VERSION 5.8 ;
BUSBITCHARS "[]" ;
DIVIDERCHAR "/" ;
UNITS
    DATABASE MICRONS 1000 ;
END UNITS

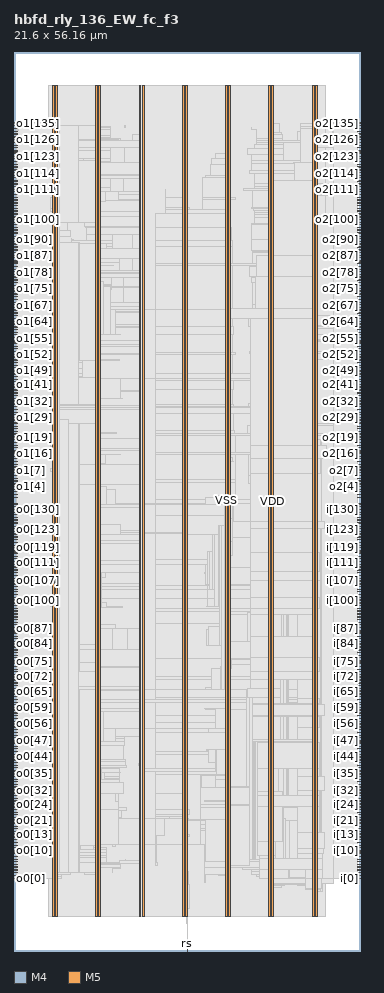
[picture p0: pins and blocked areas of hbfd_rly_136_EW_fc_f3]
MACRO hbfd_rly_136_EW_fc_f3
  FOREIGN hbfd_rly_136_EW_fc_f3 0 0 ;
  CLASS BLOCK ;
  SIZE 21.6 BY 56.16 ;
  PIN clk_in
    DIRECTION INPUT ;
    USE SIGNAL ;
    PORT
      LAYER M4 ;
        RECT  21.408 16.224 21.6 16.248 ;
    END
  END clk_in
  PIN clk_out0
    DIRECTION OUTPUT ;
    USE SIGNAL ;
    PORT
      LAYER M4 ;
        RECT  0 16.224 0.192 16.248 ;
    END
  END clk_out0
  PIN clk_out1
    DIRECTION OUTPUT ;
    USE SIGNAL ;
    PORT
      LAYER M4 ;
        RECT  0 39.984 0.192 40.008 ;
    END
  END clk_out1
  PIN clk_out2
    DIRECTION OUTPUT ;
    USE SIGNAL ;
    PORT
      LAYER M4 ;
        RECT  21.408 39.984 21.6 40.008 ;
    END
  END clk_out2
  PIN i[0]
    DIRECTION INPUT ;
    USE SIGNAL ;
    PORT
      LAYER M4 ;
        RECT  21.408 4.512 21.6 4.536 ;
    END
  END i[0]
  PIN i[100]
    DIRECTION INPUT ;
    USE SIGNAL ;
    PORT
      LAYER M4 ;
        RECT  21.408 21.888 21.6 21.912 ;
    END
  END i[100]
  PIN i[101]
    DIRECTION INPUT ;
    USE SIGNAL ;
    PORT
      LAYER M4 ;
        RECT  21.408 22.032 21.6 22.056 ;
    END
  END i[101]
  PIN i[102]
    DIRECTION INPUT ;
    USE SIGNAL ;
    PORT
      LAYER M4 ;
        RECT  21.408 22.224 21.6 22.248 ;
    END
  END i[102]
  PIN i[103]
    DIRECTION INPUT ;
    USE SIGNAL ;
    PORT
      LAYER M4 ;
        RECT  21.408 22.416 21.6 22.44 ;
    END
  END i[103]
  PIN i[104]
    DIRECTION INPUT ;
    USE SIGNAL ;
    PORT
      LAYER M4 ;
        RECT  21.408 22.56 21.6 22.584 ;
    END
  END i[104]
  PIN i[105]
    DIRECTION INPUT ;
    USE SIGNAL ;
    PORT
      LAYER M4 ;
        RECT  21.408 22.752 21.6 22.776 ;
    END
  END i[105]
  PIN i[106]
    DIRECTION INPUT ;
    USE SIGNAL ;
    PORT
      LAYER M4 ;
        RECT  21.408 22.896 21.6 22.92 ;
    END
  END i[106]
  PIN i[107]
    DIRECTION INPUT ;
    USE SIGNAL ;
    PORT
      LAYER M4 ;
        RECT  21.408 23.088 21.6 23.112 ;
    END
  END i[107]
  PIN i[108]
    DIRECTION INPUT ;
    USE SIGNAL ;
    PORT
      LAYER M4 ;
        RECT  21.408 23.232 21.6 23.256 ;
    END
  END i[108]
  PIN i[109]
    DIRECTION INPUT ;
    USE SIGNAL ;
    PORT
      LAYER M4 ;
        RECT  21.408 23.424 21.6 23.448 ;
    END
  END i[109]
  PIN i[10]
    DIRECTION INPUT ;
    USE SIGNAL ;
    PORT
      LAYER M4 ;
        RECT  21.408 6.24 21.6 6.264 ;
    END
  END i[10]
  PIN i[110]
    DIRECTION INPUT ;
    USE SIGNAL ;
    PORT
      LAYER M4 ;
        RECT  21.408 23.616 21.6 23.64 ;
    END
  END i[110]
  PIN i[111]
    DIRECTION INPUT ;
    USE SIGNAL ;
    PORT
      LAYER M4 ;
        RECT  21.408 23.76 21.6 23.784 ;
    END
  END i[111]
  PIN i[112]
    DIRECTION INPUT ;
    USE SIGNAL ;
    PORT
      LAYER M4 ;
        RECT  21.408 23.952 21.6 23.976 ;
    END
  END i[112]
  PIN i[113]
    DIRECTION INPUT ;
    USE SIGNAL ;
    PORT
      LAYER M4 ;
        RECT  21.408 24.096 21.6 24.12 ;
    END
  END i[113]
  PIN i[114]
    DIRECTION INPUT ;
    USE SIGNAL ;
    PORT
      LAYER M4 ;
        RECT  21.408 24.288 21.6 24.312 ;
    END
  END i[114]
  PIN i[115]
    DIRECTION INPUT ;
    USE SIGNAL ;
    PORT
      LAYER M4 ;
        RECT  21.408 24.48 21.6 24.504 ;
    END
  END i[115]
  PIN i[116]
    DIRECTION INPUT ;
    USE SIGNAL ;
    PORT
      LAYER M4 ;
        RECT  21.408 24.624 21.6 24.648 ;
    END
  END i[116]
  PIN i[117]
    DIRECTION INPUT ;
    USE SIGNAL ;
    PORT
      LAYER M4 ;
        RECT  21.408 24.816 21.6 24.84 ;
    END
  END i[117]
  PIN i[118]
    DIRECTION INPUT ;
    USE SIGNAL ;
    PORT
      LAYER M4 ;
        RECT  21.408 24.96 21.6 24.984 ;
    END
  END i[118]
  PIN i[119]
    DIRECTION INPUT ;
    USE SIGNAL ;
    PORT
      LAYER M4 ;
        RECT  21.408 25.152 21.6 25.176 ;
    END
  END i[119]
  PIN i[11]
    DIRECTION INPUT ;
    USE SIGNAL ;
    PORT
      LAYER M4 ;
        RECT  21.408 6.432 21.6 6.456 ;
    END
  END i[11]
  PIN i[120]
    DIRECTION INPUT ;
    USE SIGNAL ;
    PORT
      LAYER M4 ;
        RECT  21.408 25.296 21.6 25.32 ;
    END
  END i[120]
  PIN i[121]
    DIRECTION INPUT ;
    USE SIGNAL ;
    PORT
      LAYER M4 ;
        RECT  21.408 25.488 21.6 25.512 ;
    END
  END i[121]
  PIN i[122]
    DIRECTION INPUT ;
    USE SIGNAL ;
    PORT
      LAYER M4 ;
        RECT  21.408 25.68 21.6 25.704 ;
    END
  END i[122]
  PIN i[123]
    DIRECTION INPUT ;
    USE SIGNAL ;
    PORT
      LAYER M4 ;
        RECT  21.408 25.824 21.6 25.848 ;
    END
  END i[123]
  PIN i[124]
    DIRECTION INPUT ;
    USE SIGNAL ;
    PORT
      LAYER M4 ;
        RECT  21.408 26.016 21.6 26.04 ;
    END
  END i[124]
  PIN i[125]
    DIRECTION INPUT ;
    USE SIGNAL ;
    PORT
      LAYER M4 ;
        RECT  21.408 26.16 21.6 26.184 ;
    END
  END i[125]
  PIN i[126]
    DIRECTION INPUT ;
    USE SIGNAL ;
    PORT
      LAYER M4 ;
        RECT  21.408 26.352 21.6 26.376 ;
    END
  END i[126]
  PIN i[127]
    DIRECTION INPUT ;
    USE SIGNAL ;
    PORT
      LAYER M4 ;
        RECT  21.408 26.496 21.6 26.52 ;
    END
  END i[127]
  PIN i[128]
    DIRECTION INPUT ;
    USE SIGNAL ;
    PORT
      LAYER M4 ;
        RECT  21.408 26.688 21.6 26.712 ;
    END
  END i[128]
  PIN i[129]
    DIRECTION INPUT ;
    USE SIGNAL ;
    PORT
      LAYER M4 ;
        RECT  21.408 26.88 21.6 26.904 ;
    END
  END i[129]
  PIN i[12]
    DIRECTION INPUT ;
    USE SIGNAL ;
    PORT
      LAYER M4 ;
        RECT  21.408 6.576 21.6 6.6 ;
    END
  END i[12]
  PIN i[130]
    DIRECTION INPUT ;
    USE SIGNAL ;
    PORT
      LAYER M4 ;
        RECT  21.408 27.024 21.6 27.048 ;
    END
  END i[130]
  PIN i[131]
    DIRECTION INPUT ;
    USE SIGNAL ;
    PORT
      LAYER M4 ;
        RECT  21.408 27.216 21.6 27.24 ;
    END
  END i[131]
  PIN i[132]
    DIRECTION INPUT ;
    USE SIGNAL ;
    PORT
      LAYER M4 ;
        RECT  21.408 27.36 21.6 27.384 ;
    END
  END i[132]
  PIN i[133]
    DIRECTION INPUT ;
    USE SIGNAL ;
    PORT
      LAYER M4 ;
        RECT  21.408 27.552 21.6 27.576 ;
    END
  END i[133]
  PIN i[134]
    DIRECTION INPUT ;
    USE SIGNAL ;
    PORT
      LAYER M4 ;
        RECT  21.408 27.744 21.6 27.768 ;
    END
  END i[134]
  PIN i[135]
    DIRECTION INPUT ;
    USE SIGNAL ;
    PORT
      LAYER M4 ;
        RECT  21.408 27.888 21.6 27.912 ;
    END
  END i[135]
  PIN i[13]
    DIRECTION INPUT ;
    USE SIGNAL ;
    PORT
      LAYER M4 ;
        RECT  21.408 6.768 21.6 6.792 ;
    END
  END i[13]
  PIN i[14]
    DIRECTION INPUT ;
    USE SIGNAL ;
    PORT
      LAYER M4 ;
        RECT  21.408 6.96 21.6 6.984 ;
    END
  END i[14]
  PIN i[15]
    DIRECTION INPUT ;
    USE SIGNAL ;
    PORT
      LAYER M4 ;
        RECT  21.408 7.104 21.6 7.128 ;
    END
  END i[15]
  PIN i[16]
    DIRECTION INPUT ;
    USE SIGNAL ;
    PORT
      LAYER M4 ;
        RECT  21.408 7.296 21.6 7.32 ;
    END
  END i[16]
  PIN i[17]
    DIRECTION INPUT ;
    USE SIGNAL ;
    PORT
      LAYER M4 ;
        RECT  21.408 7.44 21.6 7.464 ;
    END
  END i[17]
  PIN i[18]
    DIRECTION INPUT ;
    USE SIGNAL ;
    PORT
      LAYER M4 ;
        RECT  21.408 7.632 21.6 7.656 ;
    END
  END i[18]
  PIN i[19]
    DIRECTION INPUT ;
    USE SIGNAL ;
    PORT
      LAYER M4 ;
        RECT  21.408 7.776 21.6 7.8 ;
    END
  END i[19]
  PIN i[1]
    DIRECTION INPUT ;
    USE SIGNAL ;
    PORT
      LAYER M4 ;
        RECT  21.408 4.704 21.6 4.728 ;
    END
  END i[1]
  PIN i[20]
    DIRECTION INPUT ;
    USE SIGNAL ;
    PORT
      LAYER M4 ;
        RECT  21.408 7.968 21.6 7.992 ;
    END
  END i[20]
  PIN i[21]
    DIRECTION INPUT ;
    USE SIGNAL ;
    PORT
      LAYER M4 ;
        RECT  21.408 8.16 21.6 8.184 ;
    END
  END i[21]
  PIN i[22]
    DIRECTION INPUT ;
    USE SIGNAL ;
    PORT
      LAYER M4 ;
        RECT  21.408 8.304 21.6 8.328 ;
    END
  END i[22]
  PIN i[23]
    DIRECTION INPUT ;
    USE SIGNAL ;
    PORT
      LAYER M4 ;
        RECT  21.408 8.496 21.6 8.52 ;
    END
  END i[23]
  PIN i[24]
    DIRECTION INPUT ;
    USE SIGNAL ;
    PORT
      LAYER M4 ;
        RECT  21.408 8.64 21.6 8.664 ;
    END
  END i[24]
  PIN i[25]
    DIRECTION INPUT ;
    USE SIGNAL ;
    PORT
      LAYER M4 ;
        RECT  21.408 8.832 21.6 8.856 ;
    END
  END i[25]
  PIN i[26]
    DIRECTION INPUT ;
    USE SIGNAL ;
    PORT
      LAYER M4 ;
        RECT  21.408 8.976 21.6 9 ;
    END
  END i[26]
  PIN i[27]
    DIRECTION INPUT ;
    USE SIGNAL ;
    PORT
      LAYER M4 ;
        RECT  21.408 9.168 21.6 9.192 ;
    END
  END i[27]
  PIN i[28]
    DIRECTION INPUT ;
    USE SIGNAL ;
    PORT
      LAYER M4 ;
        RECT  21.408 9.36 21.6 9.384 ;
    END
  END i[28]
  PIN i[29]
    DIRECTION INPUT ;
    USE SIGNAL ;
    PORT
      LAYER M4 ;
        RECT  21.408 9.504 21.6 9.528 ;
    END
  END i[29]
  PIN i[2]
    DIRECTION INPUT ;
    USE SIGNAL ;
    PORT
      LAYER M4 ;
        RECT  21.408 4.896 21.6 4.92 ;
    END
  END i[2]
  PIN i[30]
    DIRECTION INPUT ;
    USE SIGNAL ;
    PORT
      LAYER M4 ;
        RECT  21.408 9.696 21.6 9.72 ;
    END
  END i[30]
  PIN i[31]
    DIRECTION INPUT ;
    USE SIGNAL ;
    PORT
      LAYER M4 ;
        RECT  21.408 9.84 21.6 9.864 ;
    END
  END i[31]
  PIN i[32]
    DIRECTION INPUT ;
    USE SIGNAL ;
    PORT
      LAYER M4 ;
        RECT  21.408 10.032 21.6 10.056 ;
    END
  END i[32]
  PIN i[33]
    DIRECTION INPUT ;
    USE SIGNAL ;
    PORT
      LAYER M4 ;
        RECT  21.408 10.224 21.6 10.248 ;
    END
  END i[33]
  PIN i[34]
    DIRECTION INPUT ;
    USE SIGNAL ;
    PORT
      LAYER M4 ;
        RECT  21.408 10.368 21.6 10.392 ;
    END
  END i[34]
  PIN i[35]
    DIRECTION INPUT ;
    USE SIGNAL ;
    PORT
      LAYER M4 ;
        RECT  21.408 10.56 21.6 10.584 ;
    END
  END i[35]
  PIN i[36]
    DIRECTION INPUT ;
    USE SIGNAL ;
    PORT
      LAYER M4 ;
        RECT  21.408 10.704 21.6 10.728 ;
    END
  END i[36]
  PIN i[37]
    DIRECTION INPUT ;
    USE SIGNAL ;
    PORT
      LAYER M4 ;
        RECT  21.408 10.896 21.6 10.92 ;
    END
  END i[37]
  PIN i[38]
    DIRECTION INPUT ;
    USE SIGNAL ;
    PORT
      LAYER M4 ;
        RECT  21.408 11.04 21.6 11.064 ;
    END
  END i[38]
  PIN i[39]
    DIRECTION INPUT ;
    USE SIGNAL ;
    PORT
      LAYER M4 ;
        RECT  21.408 11.232 21.6 11.256 ;
    END
  END i[39]
  PIN i[3]
    DIRECTION INPUT ;
    USE SIGNAL ;
    PORT
      LAYER M4 ;
        RECT  21.408 5.04 21.6 5.064 ;
    END
  END i[3]
  PIN i[40]
    DIRECTION INPUT ;
    USE SIGNAL ;
    PORT
      LAYER M4 ;
        RECT  21.408 11.424 21.6 11.448 ;
    END
  END i[40]
  PIN i[41]
    DIRECTION INPUT ;
    USE SIGNAL ;
    PORT
      LAYER M4 ;
        RECT  21.408 11.568 21.6 11.592 ;
    END
  END i[41]
  PIN i[42]
    DIRECTION INPUT ;
    USE SIGNAL ;
    PORT
      LAYER M4 ;
        RECT  21.408 11.76 21.6 11.784 ;
    END
  END i[42]
  PIN i[43]
    DIRECTION INPUT ;
    USE SIGNAL ;
    PORT
      LAYER M4 ;
        RECT  21.408 11.904 21.6 11.928 ;
    END
  END i[43]
  PIN i[44]
    DIRECTION INPUT ;
    USE SIGNAL ;
    PORT
      LAYER M4 ;
        RECT  21.408 12.096 21.6 12.12 ;
    END
  END i[44]
  PIN i[45]
    DIRECTION INPUT ;
    USE SIGNAL ;
    PORT
      LAYER M4 ;
        RECT  21.408 12.24 21.6 12.264 ;
    END
  END i[45]
  PIN i[46]
    DIRECTION INPUT ;
    USE SIGNAL ;
    PORT
      LAYER M4 ;
        RECT  21.408 12.432 21.6 12.456 ;
    END
  END i[46]
  PIN i[47]
    DIRECTION INPUT ;
    USE SIGNAL ;
    PORT
      LAYER M4 ;
        RECT  21.408 12.624 21.6 12.648 ;
    END
  END i[47]
  PIN i[48]
    DIRECTION INPUT ;
    USE SIGNAL ;
    PORT
      LAYER M4 ;
        RECT  21.408 12.768 21.6 12.792 ;
    END
  END i[48]
  PIN i[49]
    DIRECTION INPUT ;
    USE SIGNAL ;
    PORT
      LAYER M4 ;
        RECT  21.408 12.96 21.6 12.984 ;
    END
  END i[49]
  PIN i[4]
    DIRECTION INPUT ;
    USE SIGNAL ;
    PORT
      LAYER M4 ;
        RECT  21.408 5.232 21.6 5.256 ;
    END
  END i[4]
  PIN i[50]
    DIRECTION INPUT ;
    USE SIGNAL ;
    PORT
      LAYER M4 ;
        RECT  21.408 13.104 21.6 13.128 ;
    END
  END i[50]
  PIN i[51]
    DIRECTION INPUT ;
    USE SIGNAL ;
    PORT
      LAYER M4 ;
        RECT  21.408 13.296 21.6 13.32 ;
    END
  END i[51]
  PIN i[52]
    DIRECTION INPUT ;
    USE SIGNAL ;
    PORT
      LAYER M4 ;
        RECT  21.408 13.44 21.6 13.464 ;
    END
  END i[52]
  PIN i[53]
    DIRECTION INPUT ;
    USE SIGNAL ;
    PORT
      LAYER M4 ;
        RECT  21.408 13.632 21.6 13.656 ;
    END
  END i[53]
  PIN i[54]
    DIRECTION INPUT ;
    USE SIGNAL ;
    PORT
      LAYER M4 ;
        RECT  21.408 13.824 21.6 13.848 ;
    END
  END i[54]
  PIN i[55]
    DIRECTION INPUT ;
    USE SIGNAL ;
    PORT
      LAYER M4 ;
        RECT  21.408 13.968 21.6 13.992 ;
    END
  END i[55]
  PIN i[56]
    DIRECTION INPUT ;
    USE SIGNAL ;
    PORT
      LAYER M4 ;
        RECT  21.408 14.16 21.6 14.184 ;
    END
  END i[56]
  PIN i[57]
    DIRECTION INPUT ;
    USE SIGNAL ;
    PORT
      LAYER M4 ;
        RECT  21.408 14.304 21.6 14.328 ;
    END
  END i[57]
  PIN i[58]
    DIRECTION INPUT ;
    USE SIGNAL ;
    PORT
      LAYER M4 ;
        RECT  21.408 14.496 21.6 14.52 ;
    END
  END i[58]
  PIN i[59]
    DIRECTION INPUT ;
    USE SIGNAL ;
    PORT
      LAYER M4 ;
        RECT  21.408 14.688 21.6 14.712 ;
    END
  END i[59]
  PIN i[5]
    DIRECTION INPUT ;
    USE SIGNAL ;
    PORT
      LAYER M4 ;
        RECT  21.408 5.376 21.6 5.4 ;
    END
  END i[5]
  PIN i[60]
    DIRECTION INPUT ;
    USE SIGNAL ;
    PORT
      LAYER M4 ;
        RECT  21.408 14.832 21.6 14.856 ;
    END
  END i[60]
  PIN i[61]
    DIRECTION INPUT ;
    USE SIGNAL ;
    PORT
      LAYER M4 ;
        RECT  21.408 15.024 21.6 15.048 ;
    END
  END i[61]
  PIN i[62]
    DIRECTION INPUT ;
    USE SIGNAL ;
    PORT
      LAYER M4 ;
        RECT  21.408 15.168 21.6 15.192 ;
    END
  END i[62]
  PIN i[63]
    DIRECTION INPUT ;
    USE SIGNAL ;
    PORT
      LAYER M4 ;
        RECT  21.408 15.36 21.6 15.384 ;
    END
  END i[63]
  PIN i[64]
    DIRECTION INPUT ;
    USE SIGNAL ;
    PORT
      LAYER M4 ;
        RECT  21.408 15.504 21.6 15.528 ;
    END
  END i[64]
  PIN i[65]
    DIRECTION INPUT ;
    USE SIGNAL ;
    PORT
      LAYER M4 ;
        RECT  21.408 15.696 21.6 15.72 ;
    END
  END i[65]
  PIN i[66]
    DIRECTION INPUT ;
    USE SIGNAL ;
    PORT
      LAYER M4 ;
        RECT  21.408 15.888 21.6 15.912 ;
    END
  END i[66]
  PIN i[67]
    DIRECTION INPUT ;
    USE SIGNAL ;
    PORT
      LAYER M4 ;
        RECT  21.408 16.032 21.6 16.056 ;
    END
  END i[67]
  PIN i[68]
    DIRECTION INPUT ;
    USE SIGNAL ;
    PORT
      LAYER M4 ;
        RECT  21.408 16.368 21.6 16.392 ;
    END
  END i[68]
  PIN i[69]
    DIRECTION INPUT ;
    USE SIGNAL ;
    PORT
      LAYER M4 ;
        RECT  21.408 16.56 21.6 16.584 ;
    END
  END i[69]
  PIN i[6]
    DIRECTION INPUT ;
    USE SIGNAL ;
    PORT
      LAYER M4 ;
        RECT  21.408 5.568 21.6 5.592 ;
    END
  END i[6]
  PIN i[70]
    DIRECTION INPUT ;
    USE SIGNAL ;
    PORT
      LAYER M4 ;
        RECT  21.408 16.704 21.6 16.728 ;
    END
  END i[70]
  PIN i[71]
    DIRECTION INPUT ;
    USE SIGNAL ;
    PORT
      LAYER M4 ;
        RECT  21.408 16.896 21.6 16.92 ;
    END
  END i[71]
  PIN i[72]
    DIRECTION INPUT ;
    USE SIGNAL ;
    PORT
      LAYER M4 ;
        RECT  21.408 17.088 21.6 17.112 ;
    END
  END i[72]
  PIN i[73]
    DIRECTION INPUT ;
    USE SIGNAL ;
    PORT
      LAYER M4 ;
        RECT  21.408 17.232 21.6 17.256 ;
    END
  END i[73]
  PIN i[74]
    DIRECTION INPUT ;
    USE SIGNAL ;
    PORT
      LAYER M4 ;
        RECT  21.408 17.424 21.6 17.448 ;
    END
  END i[74]
  PIN i[75]
    DIRECTION INPUT ;
    USE SIGNAL ;
    PORT
      LAYER M4 ;
        RECT  21.408 17.568 21.6 17.592 ;
    END
  END i[75]
  PIN i[76]
    DIRECTION INPUT ;
    USE SIGNAL ;
    PORT
      LAYER M4 ;
        RECT  21.408 17.76 21.6 17.784 ;
    END
  END i[76]
  PIN i[77]
    DIRECTION INPUT ;
    USE SIGNAL ;
    PORT
      LAYER M4 ;
        RECT  21.408 17.952 21.6 17.976 ;
    END
  END i[77]
  PIN i[78]
    DIRECTION INPUT ;
    USE SIGNAL ;
    PORT
      LAYER M4 ;
        RECT  21.408 18.096 21.6 18.12 ;
    END
  END i[78]
  PIN i[79]
    DIRECTION INPUT ;
    USE SIGNAL ;
    PORT
      LAYER M4 ;
        RECT  21.408 18.288 21.6 18.312 ;
    END
  END i[79]
  PIN i[7]
    DIRECTION INPUT ;
    USE SIGNAL ;
    PORT
      LAYER M4 ;
        RECT  21.408 5.712 21.6 5.736 ;
    END
  END i[7]
  PIN i[80]
    DIRECTION INPUT ;
    USE SIGNAL ;
    PORT
      LAYER M4 ;
        RECT  21.408 18.432 21.6 18.456 ;
    END
  END i[80]
  PIN i[81]
    DIRECTION INPUT ;
    USE SIGNAL ;
    PORT
      LAYER M4 ;
        RECT  21.408 18.624 21.6 18.648 ;
    END
  END i[81]
  PIN i[82]
    DIRECTION INPUT ;
    USE SIGNAL ;
    PORT
      LAYER M4 ;
        RECT  21.408 18.768 21.6 18.792 ;
    END
  END i[82]
  PIN i[83]
    DIRECTION INPUT ;
    USE SIGNAL ;
    PORT
      LAYER M4 ;
        RECT  21.408 18.96 21.6 18.984 ;
    END
  END i[83]
  PIN i[84]
    DIRECTION INPUT ;
    USE SIGNAL ;
    PORT
      LAYER M4 ;
        RECT  21.408 19.152 21.6 19.176 ;
    END
  END i[84]
  PIN i[85]
    DIRECTION INPUT ;
    USE SIGNAL ;
    PORT
      LAYER M4 ;
        RECT  21.408 19.296 21.6 19.32 ;
    END
  END i[85]
  PIN i[86]
    DIRECTION INPUT ;
    USE SIGNAL ;
    PORT
      LAYER M4 ;
        RECT  21.408 19.488 21.6 19.512 ;
    END
  END i[86]
  PIN i[87]
    DIRECTION INPUT ;
    USE SIGNAL ;
    PORT
      LAYER M4 ;
        RECT  21.408 19.632 21.6 19.656 ;
    END
  END i[87]
  PIN i[88]
    DIRECTION INPUT ;
    USE SIGNAL ;
    PORT
      LAYER M4 ;
        RECT  21.408 19.824 21.6 19.848 ;
    END
  END i[88]
  PIN i[89]
    DIRECTION INPUT ;
    USE SIGNAL ;
    PORT
      LAYER M4 ;
        RECT  21.408 19.968 21.6 19.992 ;
    END
  END i[89]
  PIN i[8]
    DIRECTION INPUT ;
    USE SIGNAL ;
    PORT
      LAYER M4 ;
        RECT  21.408 5.904 21.6 5.928 ;
    END
  END i[8]
  PIN i[90]
    DIRECTION INPUT ;
    USE SIGNAL ;
    PORT
      LAYER M4 ;
        RECT  21.408 20.16 21.6 20.184 ;
    END
  END i[90]
  PIN i[91]
    DIRECTION INPUT ;
    USE SIGNAL ;
    PORT
      LAYER M4 ;
        RECT  21.408 20.352 21.6 20.376 ;
    END
  END i[91]
  PIN i[92]
    DIRECTION INPUT ;
    USE SIGNAL ;
    PORT
      LAYER M4 ;
        RECT  21.408 20.496 21.6 20.52 ;
    END
  END i[92]
  PIN i[93]
    DIRECTION INPUT ;
    USE SIGNAL ;
    PORT
      LAYER M4 ;
        RECT  21.408 20.688 21.6 20.712 ;
    END
  END i[93]
  PIN i[94]
    DIRECTION INPUT ;
    USE SIGNAL ;
    PORT
      LAYER M4 ;
        RECT  21.408 20.832 21.6 20.856 ;
    END
  END i[94]
  PIN i[95]
    DIRECTION INPUT ;
    USE SIGNAL ;
    PORT
      LAYER M4 ;
        RECT  21.408 21.024 21.6 21.048 ;
    END
  END i[95]
  PIN i[96]
    DIRECTION INPUT ;
    USE SIGNAL ;
    PORT
      LAYER M4 ;
        RECT  21.408 21.216 21.6 21.24 ;
    END
  END i[96]
  PIN i[97]
    DIRECTION INPUT ;
    USE SIGNAL ;
    PORT
      LAYER M4 ;
        RECT  21.408 21.36 21.6 21.384 ;
    END
  END i[97]
  PIN i[98]
    DIRECTION INPUT ;
    USE SIGNAL ;
    PORT
      LAYER M4 ;
        RECT  21.408 21.552 21.6 21.576 ;
    END
  END i[98]
  PIN i[99]
    DIRECTION INPUT ;
    USE SIGNAL ;
    PORT
      LAYER M4 ;
        RECT  21.408 21.696 21.6 21.72 ;
    END
  END i[99]
  PIN i[9]
    DIRECTION INPUT ;
    USE SIGNAL ;
    PORT
      LAYER M4 ;
        RECT  21.408 6.096 21.6 6.12 ;
    END
  END i[9]
  PIN o0[0]
    DIRECTION OUTPUT ;
    USE SIGNAL ;
    PORT
      LAYER M4 ;
        RECT  0 4.512 0.192 4.536 ;
    END
  END o0[0]
  PIN o0[100]
    DIRECTION OUTPUT ;
    USE SIGNAL ;
    PORT
      LAYER M4 ;
        RECT  0 21.888 0.192 21.912 ;
    END
  END o0[100]
  PIN o0[101]
    DIRECTION OUTPUT ;
    USE SIGNAL ;
    PORT
      LAYER M4 ;
        RECT  0 22.032 0.192 22.056 ;
    END
  END o0[101]
  PIN o0[102]
    DIRECTION OUTPUT ;
    USE SIGNAL ;
    PORT
      LAYER M4 ;
        RECT  0 22.224 0.192 22.248 ;
    END
  END o0[102]
  PIN o0[103]
    DIRECTION OUTPUT ;
    USE SIGNAL ;
    PORT
      LAYER M4 ;
        RECT  0 22.416 0.192 22.44 ;
    END
  END o0[103]
  PIN o0[104]
    DIRECTION OUTPUT ;
    USE SIGNAL ;
    PORT
      LAYER M4 ;
        RECT  0 22.56 0.192 22.584 ;
    END
  END o0[104]
  PIN o0[105]
    DIRECTION OUTPUT ;
    USE SIGNAL ;
    PORT
      LAYER M4 ;
        RECT  0 22.752 0.192 22.776 ;
    END
  END o0[105]
  PIN o0[106]
    DIRECTION OUTPUT ;
    USE SIGNAL ;
    PORT
      LAYER M4 ;
        RECT  0 22.896 0.192 22.92 ;
    END
  END o0[106]
  PIN o0[107]
    DIRECTION OUTPUT ;
    USE SIGNAL ;
    PORT
      LAYER M4 ;
        RECT  0 23.088 0.192 23.112 ;
    END
  END o0[107]
  PIN o0[108]
    DIRECTION OUTPUT ;
    USE SIGNAL ;
    PORT
      LAYER M4 ;
        RECT  0 23.232 0.192 23.256 ;
    END
  END o0[108]
  PIN o0[109]
    DIRECTION OUTPUT ;
    USE SIGNAL ;
    PORT
      LAYER M4 ;
        RECT  0 23.424 0.192 23.448 ;
    END
  END o0[109]
  PIN o0[10]
    DIRECTION OUTPUT ;
    USE SIGNAL ;
    PORT
      LAYER M4 ;
        RECT  0 6.24 0.192 6.264 ;
    END
  END o0[10]
  PIN o0[110]
    DIRECTION OUTPUT ;
    USE SIGNAL ;
    PORT
      LAYER M4 ;
        RECT  0 23.616 0.192 23.64 ;
    END
  END o0[110]
  PIN o0[111]
    DIRECTION OUTPUT ;
    USE SIGNAL ;
    PORT
      LAYER M4 ;
        RECT  0 23.76 0.192 23.784 ;
    END
  END o0[111]
  PIN o0[112]
    DIRECTION OUTPUT ;
    USE SIGNAL ;
    PORT
      LAYER M4 ;
        RECT  0 23.952 0.192 23.976 ;
    END
  END o0[112]
  PIN o0[113]
    DIRECTION OUTPUT ;
    USE SIGNAL ;
    PORT
      LAYER M4 ;
        RECT  0 24.096 0.192 24.12 ;
    END
  END o0[113]
  PIN o0[114]
    DIRECTION OUTPUT ;
    USE SIGNAL ;
    PORT
      LAYER M4 ;
        RECT  0 24.288 0.192 24.312 ;
    END
  END o0[114]
  PIN o0[115]
    DIRECTION OUTPUT ;
    USE SIGNAL ;
    PORT
      LAYER M4 ;
        RECT  0 24.48 0.192 24.504 ;
    END
  END o0[115]
  PIN o0[116]
    DIRECTION OUTPUT ;
    USE SIGNAL ;
    PORT
      LAYER M4 ;
        RECT  0 24.624 0.192 24.648 ;
    END
  END o0[116]
  PIN o0[117]
    DIRECTION OUTPUT ;
    USE SIGNAL ;
    PORT
      LAYER M4 ;
        RECT  0 24.816 0.192 24.84 ;
    END
  END o0[117]
  PIN o0[118]
    DIRECTION OUTPUT ;
    USE SIGNAL ;
    PORT
      LAYER M4 ;
        RECT  0 24.96 0.192 24.984 ;
    END
  END o0[118]
  PIN o0[119]
    DIRECTION OUTPUT ;
    USE SIGNAL ;
    PORT
      LAYER M4 ;
        RECT  0 25.152 0.192 25.176 ;
    END
  END o0[119]
  PIN o0[11]
    DIRECTION OUTPUT ;
    USE SIGNAL ;
    PORT
      LAYER M4 ;
        RECT  0 6.432 0.192 6.456 ;
    END
  END o0[11]
  PIN o0[120]
    DIRECTION OUTPUT ;
    USE SIGNAL ;
    PORT
      LAYER M4 ;
        RECT  0 25.296 0.192 25.32 ;
    END
  END o0[120]
  PIN o0[121]
    DIRECTION OUTPUT ;
    USE SIGNAL ;
    PORT
      LAYER M4 ;
        RECT  0 25.488 0.192 25.512 ;
    END
  END o0[121]
  PIN o0[122]
    DIRECTION OUTPUT ;
    USE SIGNAL ;
    PORT
      LAYER M4 ;
        RECT  0 25.68 0.192 25.704 ;
    END
  END o0[122]
  PIN o0[123]
    DIRECTION OUTPUT ;
    USE SIGNAL ;
    PORT
      LAYER M4 ;
        RECT  0 25.824 0.192 25.848 ;
    END
  END o0[123]
  PIN o0[124]
    DIRECTION OUTPUT ;
    USE SIGNAL ;
    PORT
      LAYER M4 ;
        RECT  0 26.016 0.192 26.04 ;
    END
  END o0[124]
  PIN o0[125]
    DIRECTION OUTPUT ;
    USE SIGNAL ;
    PORT
      LAYER M4 ;
        RECT  0 26.16 0.192 26.184 ;
    END
  END o0[125]
  PIN o0[126]
    DIRECTION OUTPUT ;
    USE SIGNAL ;
    PORT
      LAYER M4 ;
        RECT  0 26.352 0.192 26.376 ;
    END
  END o0[126]
  PIN o0[127]
    DIRECTION OUTPUT ;
    USE SIGNAL ;
    PORT
      LAYER M4 ;
        RECT  0 26.496 0.192 26.52 ;
    END
  END o0[127]
  PIN o0[128]
    DIRECTION OUTPUT ;
    USE SIGNAL ;
    PORT
      LAYER M4 ;
        RECT  0 26.688 0.192 26.712 ;
    END
  END o0[128]
  PIN o0[129]
    DIRECTION OUTPUT ;
    USE SIGNAL ;
    PORT
      LAYER M4 ;
        RECT  0 26.88 0.192 26.904 ;
    END
  END o0[129]
  PIN o0[12]
    DIRECTION OUTPUT ;
    USE SIGNAL ;
    PORT
      LAYER M4 ;
        RECT  0 6.576 0.192 6.6 ;
    END
  END o0[12]
  PIN o0[130]
    DIRECTION OUTPUT ;
    USE SIGNAL ;
    PORT
      LAYER M4 ;
        RECT  0 27.024 0.192 27.048 ;
    END
  END o0[130]
  PIN o0[131]
    DIRECTION OUTPUT ;
    USE SIGNAL ;
    PORT
      LAYER M4 ;
        RECT  0 27.216 0.192 27.24 ;
    END
  END o0[131]
  PIN o0[132]
    DIRECTION OUTPUT ;
    USE SIGNAL ;
    PORT
      LAYER M4 ;
        RECT  0 27.36 0.192 27.384 ;
    END
  END o0[132]
  PIN o0[133]
    DIRECTION OUTPUT ;
    USE SIGNAL ;
    PORT
      LAYER M4 ;
        RECT  0 27.552 0.192 27.576 ;
    END
  END o0[133]
  PIN o0[134]
    DIRECTION OUTPUT ;
    USE SIGNAL ;
    PORT
      LAYER M4 ;
        RECT  0 27.744 0.192 27.768 ;
    END
  END o0[134]
  PIN o0[135]
    DIRECTION OUTPUT ;
    USE SIGNAL ;
    PORT
      LAYER M4 ;
        RECT  0 27.888 0.192 27.912 ;
    END
  END o0[135]
  PIN o0[13]
    DIRECTION OUTPUT ;
    USE SIGNAL ;
    PORT
      LAYER M4 ;
        RECT  0 6.768 0.192 6.792 ;
    END
  END o0[13]
  PIN o0[14]
    DIRECTION OUTPUT ;
    USE SIGNAL ;
    PORT
      LAYER M4 ;
        RECT  0 6.96 0.192 6.984 ;
    END
  END o0[14]
  PIN o0[15]
    DIRECTION OUTPUT ;
    USE SIGNAL ;
    PORT
      LAYER M4 ;
        RECT  0 7.104 0.192 7.128 ;
    END
  END o0[15]
  PIN o0[16]
    DIRECTION OUTPUT ;
    USE SIGNAL ;
    PORT
      LAYER M4 ;
        RECT  0 7.296 0.192 7.32 ;
    END
  END o0[16]
  PIN o0[17]
    DIRECTION OUTPUT ;
    USE SIGNAL ;
    PORT
      LAYER M4 ;
        RECT  0 7.44 0.192 7.464 ;
    END
  END o0[17]
  PIN o0[18]
    DIRECTION OUTPUT ;
    USE SIGNAL ;
    PORT
      LAYER M4 ;
        RECT  0 7.632 0.192 7.656 ;
    END
  END o0[18]
  PIN o0[19]
    DIRECTION OUTPUT ;
    USE SIGNAL ;
    PORT
      LAYER M4 ;
        RECT  0 7.776 0.192 7.8 ;
    END
  END o0[19]
  PIN o0[1]
    DIRECTION OUTPUT ;
    USE SIGNAL ;
    PORT
      LAYER M4 ;
        RECT  0 4.704 0.192 4.728 ;
    END
  END o0[1]
  PIN o0[20]
    DIRECTION OUTPUT ;
    USE SIGNAL ;
    PORT
      LAYER M4 ;
        RECT  0 7.968 0.192 7.992 ;
    END
  END o0[20]
  PIN o0[21]
    DIRECTION OUTPUT ;
    USE SIGNAL ;
    PORT
      LAYER M4 ;
        RECT  0 8.16 0.192 8.184 ;
    END
  END o0[21]
  PIN o0[22]
    DIRECTION OUTPUT ;
    USE SIGNAL ;
    PORT
      LAYER M4 ;
        RECT  0 8.304 0.192 8.328 ;
    END
  END o0[22]
  PIN o0[23]
    DIRECTION OUTPUT ;
    USE SIGNAL ;
    PORT
      LAYER M4 ;
        RECT  0 8.496 0.192 8.52 ;
    END
  END o0[23]
  PIN o0[24]
    DIRECTION OUTPUT ;
    USE SIGNAL ;
    PORT
      LAYER M4 ;
        RECT  0 8.64 0.192 8.664 ;
    END
  END o0[24]
  PIN o0[25]
    DIRECTION OUTPUT ;
    USE SIGNAL ;
    PORT
      LAYER M4 ;
        RECT  0 8.832 0.192 8.856 ;
    END
  END o0[25]
  PIN o0[26]
    DIRECTION OUTPUT ;
    USE SIGNAL ;
    PORT
      LAYER M4 ;
        RECT  0 8.976 0.192 9 ;
    END
  END o0[26]
  PIN o0[27]
    DIRECTION OUTPUT ;
    USE SIGNAL ;
    PORT
      LAYER M4 ;
        RECT  0 9.168 0.192 9.192 ;
    END
  END o0[27]
  PIN o0[28]
    DIRECTION OUTPUT ;
    USE SIGNAL ;
    PORT
      LAYER M4 ;
        RECT  0 9.36 0.192 9.384 ;
    END
  END o0[28]
  PIN o0[29]
    DIRECTION OUTPUT ;
    USE SIGNAL ;
    PORT
      LAYER M4 ;
        RECT  0 9.504 0.192 9.528 ;
    END
  END o0[29]
  PIN o0[2]
    DIRECTION OUTPUT ;
    USE SIGNAL ;
    PORT
      LAYER M4 ;
        RECT  0 4.896 0.192 4.92 ;
    END
  END o0[2]
  PIN o0[30]
    DIRECTION OUTPUT ;
    USE SIGNAL ;
    PORT
      LAYER M4 ;
        RECT  0 9.696 0.192 9.72 ;
    END
  END o0[30]
  PIN o0[31]
    DIRECTION OUTPUT ;
    USE SIGNAL ;
    PORT
      LAYER M4 ;
        RECT  0 9.84 0.192 9.864 ;
    END
  END o0[31]
  PIN o0[32]
    DIRECTION OUTPUT ;
    USE SIGNAL ;
    PORT
      LAYER M4 ;
        RECT  0 10.032 0.192 10.056 ;
    END
  END o0[32]
  PIN o0[33]
    DIRECTION OUTPUT ;
    USE SIGNAL ;
    PORT
      LAYER M4 ;
        RECT  0 10.224 0.192 10.248 ;
    END
  END o0[33]
  PIN o0[34]
    DIRECTION OUTPUT ;
    USE SIGNAL ;
    PORT
      LAYER M4 ;
        RECT  0 10.368 0.192 10.392 ;
    END
  END o0[34]
  PIN o0[35]
    DIRECTION OUTPUT ;
    USE SIGNAL ;
    PORT
      LAYER M4 ;
        RECT  0 10.56 0.192 10.584 ;
    END
  END o0[35]
  PIN o0[36]
    DIRECTION OUTPUT ;
    USE SIGNAL ;
    PORT
      LAYER M4 ;
        RECT  0 10.704 0.192 10.728 ;
    END
  END o0[36]
  PIN o0[37]
    DIRECTION OUTPUT ;
    USE SIGNAL ;
    PORT
      LAYER M4 ;
        RECT  0 10.896 0.192 10.92 ;
    END
  END o0[37]
  PIN o0[38]
    DIRECTION OUTPUT ;
    USE SIGNAL ;
    PORT
      LAYER M4 ;
        RECT  0 11.04 0.192 11.064 ;
    END
  END o0[38]
  PIN o0[39]
    DIRECTION OUTPUT ;
    USE SIGNAL ;
    PORT
      LAYER M4 ;
        RECT  0 11.232 0.192 11.256 ;
    END
  END o0[39]
  PIN o0[3]
    DIRECTION OUTPUT ;
    USE SIGNAL ;
    PORT
      LAYER M4 ;
        RECT  0 5.04 0.192 5.064 ;
    END
  END o0[3]
  PIN o0[40]
    DIRECTION OUTPUT ;
    USE SIGNAL ;
    PORT
      LAYER M4 ;
        RECT  0 11.424 0.192 11.448 ;
    END
  END o0[40]
  PIN o0[41]
    DIRECTION OUTPUT ;
    USE SIGNAL ;
    PORT
      LAYER M4 ;
        RECT  0 11.568 0.192 11.592 ;
    END
  END o0[41]
  PIN o0[42]
    DIRECTION OUTPUT ;
    USE SIGNAL ;
    PORT
      LAYER M4 ;
        RECT  0 11.76 0.192 11.784 ;
    END
  END o0[42]
  PIN o0[43]
    DIRECTION OUTPUT ;
    USE SIGNAL ;
    PORT
      LAYER M4 ;
        RECT  0 11.904 0.192 11.928 ;
    END
  END o0[43]
  PIN o0[44]
    DIRECTION OUTPUT ;
    USE SIGNAL ;
    PORT
      LAYER M4 ;
        RECT  0 12.096 0.192 12.12 ;
    END
  END o0[44]
  PIN o0[45]
    DIRECTION OUTPUT ;
    USE SIGNAL ;
    PORT
      LAYER M4 ;
        RECT  0 12.24 0.192 12.264 ;
    END
  END o0[45]
  PIN o0[46]
    DIRECTION OUTPUT ;
    USE SIGNAL ;
    PORT
      LAYER M4 ;
        RECT  0 12.432 0.192 12.456 ;
    END
  END o0[46]
  PIN o0[47]
    DIRECTION OUTPUT ;
    USE SIGNAL ;
    PORT
      LAYER M4 ;
        RECT  0 12.624 0.192 12.648 ;
    END
  END o0[47]
  PIN o0[48]
    DIRECTION OUTPUT ;
    USE SIGNAL ;
    PORT
      LAYER M4 ;
        RECT  0 12.768 0.192 12.792 ;
    END
  END o0[48]
  PIN o0[49]
    DIRECTION OUTPUT ;
    USE SIGNAL ;
    PORT
      LAYER M4 ;
        RECT  0 12.96 0.192 12.984 ;
    END
  END o0[49]
  PIN o0[4]
    DIRECTION OUTPUT ;
    USE SIGNAL ;
    PORT
      LAYER M4 ;
        RECT  0 5.232 0.192 5.256 ;
    END
  END o0[4]
  PIN o0[50]
    DIRECTION OUTPUT ;
    USE SIGNAL ;
    PORT
      LAYER M4 ;
        RECT  0 13.104 0.192 13.128 ;
    END
  END o0[50]
  PIN o0[51]
    DIRECTION OUTPUT ;
    USE SIGNAL ;
    PORT
      LAYER M4 ;
        RECT  0 13.296 0.192 13.32 ;
    END
  END o0[51]
  PIN o0[52]
    DIRECTION OUTPUT ;
    USE SIGNAL ;
    PORT
      LAYER M4 ;
        RECT  0 13.44 0.192 13.464 ;
    END
  END o0[52]
  PIN o0[53]
    DIRECTION OUTPUT ;
    USE SIGNAL ;
    PORT
      LAYER M4 ;
        RECT  0 13.632 0.192 13.656 ;
    END
  END o0[53]
  PIN o0[54]
    DIRECTION OUTPUT ;
    USE SIGNAL ;
    PORT
      LAYER M4 ;
        RECT  0 13.824 0.192 13.848 ;
    END
  END o0[54]
  PIN o0[55]
    DIRECTION OUTPUT ;
    USE SIGNAL ;
    PORT
      LAYER M4 ;
        RECT  0 13.968 0.192 13.992 ;
    END
  END o0[55]
  PIN o0[56]
    DIRECTION OUTPUT ;
    USE SIGNAL ;
    PORT
      LAYER M4 ;
        RECT  0 14.16 0.192 14.184 ;
    END
  END o0[56]
  PIN o0[57]
    DIRECTION OUTPUT ;
    USE SIGNAL ;
    PORT
      LAYER M4 ;
        RECT  0 14.304 0.192 14.328 ;
    END
  END o0[57]
  PIN o0[58]
    DIRECTION OUTPUT ;
    USE SIGNAL ;
    PORT
      LAYER M4 ;
        RECT  0 14.496 0.192 14.52 ;
    END
  END o0[58]
  PIN o0[59]
    DIRECTION OUTPUT ;
    USE SIGNAL ;
    PORT
      LAYER M4 ;
        RECT  0 14.688 0.192 14.712 ;
    END
  END o0[59]
  PIN o0[5]
    DIRECTION OUTPUT ;
    USE SIGNAL ;
    PORT
      LAYER M4 ;
        RECT  0 5.376 0.192 5.4 ;
    END
  END o0[5]
  PIN o0[60]
    DIRECTION OUTPUT ;
    USE SIGNAL ;
    PORT
      LAYER M4 ;
        RECT  0 14.832 0.192 14.856 ;
    END
  END o0[60]
  PIN o0[61]
    DIRECTION OUTPUT ;
    USE SIGNAL ;
    PORT
      LAYER M4 ;
        RECT  0 15.024 0.192 15.048 ;
    END
  END o0[61]
  PIN o0[62]
    DIRECTION OUTPUT ;
    USE SIGNAL ;
    PORT
      LAYER M4 ;
        RECT  0 15.168 0.192 15.192 ;
    END
  END o0[62]
  PIN o0[63]
    DIRECTION OUTPUT ;
    USE SIGNAL ;
    PORT
      LAYER M4 ;
        RECT  0 15.36 0.192 15.384 ;
    END
  END o0[63]
  PIN o0[64]
    DIRECTION OUTPUT ;
    USE SIGNAL ;
    PORT
      LAYER M4 ;
        RECT  0 15.504 0.192 15.528 ;
    END
  END o0[64]
  PIN o0[65]
    DIRECTION OUTPUT ;
    USE SIGNAL ;
    PORT
      LAYER M4 ;
        RECT  0 15.696 0.192 15.72 ;
    END
  END o0[65]
  PIN o0[66]
    DIRECTION OUTPUT ;
    USE SIGNAL ;
    PORT
      LAYER M4 ;
        RECT  0 15.888 0.192 15.912 ;
    END
  END o0[66]
  PIN o0[67]
    DIRECTION OUTPUT ;
    USE SIGNAL ;
    PORT
      LAYER M4 ;
        RECT  0 16.032 0.192 16.056 ;
    END
  END o0[67]
  PIN o0[68]
    DIRECTION OUTPUT ;
    USE SIGNAL ;
    PORT
      LAYER M4 ;
        RECT  0 16.368 0.192 16.392 ;
    END
  END o0[68]
  PIN o0[69]
    DIRECTION OUTPUT ;
    USE SIGNAL ;
    PORT
      LAYER M4 ;
        RECT  0 16.56 0.192 16.584 ;
    END
  END o0[69]
  PIN o0[6]
    DIRECTION OUTPUT ;
    USE SIGNAL ;
    PORT
      LAYER M4 ;
        RECT  0 5.568 0.192 5.592 ;
    END
  END o0[6]
  PIN o0[70]
    DIRECTION OUTPUT ;
    USE SIGNAL ;
    PORT
      LAYER M4 ;
        RECT  0 16.704 0.192 16.728 ;
    END
  END o0[70]
  PIN o0[71]
    DIRECTION OUTPUT ;
    USE SIGNAL ;
    PORT
      LAYER M4 ;
        RECT  0 16.896 0.192 16.92 ;
    END
  END o0[71]
  PIN o0[72]
    DIRECTION OUTPUT ;
    USE SIGNAL ;
    PORT
      LAYER M4 ;
        RECT  0 17.088 0.192 17.112 ;
    END
  END o0[72]
  PIN o0[73]
    DIRECTION OUTPUT ;
    USE SIGNAL ;
    PORT
      LAYER M4 ;
        RECT  0 17.232 0.192 17.256 ;
    END
  END o0[73]
  PIN o0[74]
    DIRECTION OUTPUT ;
    USE SIGNAL ;
    PORT
      LAYER M4 ;
        RECT  0 17.424 0.192 17.448 ;
    END
  END o0[74]
  PIN o0[75]
    DIRECTION OUTPUT ;
    USE SIGNAL ;
    PORT
      LAYER M4 ;
        RECT  0 17.568 0.192 17.592 ;
    END
  END o0[75]
  PIN o0[76]
    DIRECTION OUTPUT ;
    USE SIGNAL ;
    PORT
      LAYER M4 ;
        RECT  0 17.76 0.192 17.784 ;
    END
  END o0[76]
  PIN o0[77]
    DIRECTION OUTPUT ;
    USE SIGNAL ;
    PORT
      LAYER M4 ;
        RECT  0 17.952 0.192 17.976 ;
    END
  END o0[77]
  PIN o0[78]
    DIRECTION OUTPUT ;
    USE SIGNAL ;
    PORT
      LAYER M4 ;
        RECT  0 18.096 0.192 18.12 ;
    END
  END o0[78]
  PIN o0[79]
    DIRECTION OUTPUT ;
    USE SIGNAL ;
    PORT
      LAYER M4 ;
        RECT  0 18.288 0.192 18.312 ;
    END
  END o0[79]
  PIN o0[7]
    DIRECTION OUTPUT ;
    USE SIGNAL ;
    PORT
      LAYER M4 ;
        RECT  0 5.712 0.192 5.736 ;
    END
  END o0[7]
  PIN o0[80]
    DIRECTION OUTPUT ;
    USE SIGNAL ;
    PORT
      LAYER M4 ;
        RECT  0 18.432 0.192 18.456 ;
    END
  END o0[80]
  PIN o0[81]
    DIRECTION OUTPUT ;
    USE SIGNAL ;
    PORT
      LAYER M4 ;
        RECT  0 18.624 0.192 18.648 ;
    END
  END o0[81]
  PIN o0[82]
    DIRECTION OUTPUT ;
    USE SIGNAL ;
    PORT
      LAYER M4 ;
        RECT  0 18.768 0.192 18.792 ;
    END
  END o0[82]
  PIN o0[83]
    DIRECTION OUTPUT ;
    USE SIGNAL ;
    PORT
      LAYER M4 ;
        RECT  0 18.96 0.192 18.984 ;
    END
  END o0[83]
  PIN o0[84]
    DIRECTION OUTPUT ;
    USE SIGNAL ;
    PORT
      LAYER M4 ;
        RECT  0 19.152 0.192 19.176 ;
    END
  END o0[84]
  PIN o0[85]
    DIRECTION OUTPUT ;
    USE SIGNAL ;
    PORT
      LAYER M4 ;
        RECT  0 19.296 0.192 19.32 ;
    END
  END o0[85]
  PIN o0[86]
    DIRECTION OUTPUT ;
    USE SIGNAL ;
    PORT
      LAYER M4 ;
        RECT  0 19.488 0.192 19.512 ;
    END
  END o0[86]
  PIN o0[87]
    DIRECTION OUTPUT ;
    USE SIGNAL ;
    PORT
      LAYER M4 ;
        RECT  0 19.632 0.192 19.656 ;
    END
  END o0[87]
  PIN o0[88]
    DIRECTION OUTPUT ;
    USE SIGNAL ;
    PORT
      LAYER M4 ;
        RECT  0 19.824 0.192 19.848 ;
    END
  END o0[88]
  PIN o0[89]
    DIRECTION OUTPUT ;
    USE SIGNAL ;
    PORT
      LAYER M4 ;
        RECT  0 19.968 0.192 19.992 ;
    END
  END o0[89]
  PIN o0[8]
    DIRECTION OUTPUT ;
    USE SIGNAL ;
    PORT
      LAYER M4 ;
        RECT  0 5.904 0.192 5.928 ;
    END
  END o0[8]
  PIN o0[90]
    DIRECTION OUTPUT ;
    USE SIGNAL ;
    PORT
      LAYER M4 ;
        RECT  0 20.16 0.192 20.184 ;
    END
  END o0[90]
  PIN o0[91]
    DIRECTION OUTPUT ;
    USE SIGNAL ;
    PORT
      LAYER M4 ;
        RECT  0 20.352 0.192 20.376 ;
    END
  END o0[91]
  PIN o0[92]
    DIRECTION OUTPUT ;
    USE SIGNAL ;
    PORT
      LAYER M4 ;
        RECT  0 20.496 0.192 20.52 ;
    END
  END o0[92]
  PIN o0[93]
    DIRECTION OUTPUT ;
    USE SIGNAL ;
    PORT
      LAYER M4 ;
        RECT  0 20.688 0.192 20.712 ;
    END
  END o0[93]
  PIN o0[94]
    DIRECTION OUTPUT ;
    USE SIGNAL ;
    PORT
      LAYER M4 ;
        RECT  0 20.832 0.192 20.856 ;
    END
  END o0[94]
  PIN o0[95]
    DIRECTION OUTPUT ;
    USE SIGNAL ;
    PORT
      LAYER M4 ;
        RECT  0 21.024 0.192 21.048 ;
    END
  END o0[95]
  PIN o0[96]
    DIRECTION OUTPUT ;
    USE SIGNAL ;
    PORT
      LAYER M4 ;
        RECT  0 21.216 0.192 21.24 ;
    END
  END o0[96]
  PIN o0[97]
    DIRECTION OUTPUT ;
    USE SIGNAL ;
    PORT
      LAYER M4 ;
        RECT  0 21.36 0.192 21.384 ;
    END
  END o0[97]
  PIN o0[98]
    DIRECTION OUTPUT ;
    USE SIGNAL ;
    PORT
      LAYER M4 ;
        RECT  0 21.552 0.192 21.576 ;
    END
  END o0[98]
  PIN o0[99]
    DIRECTION OUTPUT ;
    USE SIGNAL ;
    PORT
      LAYER M4 ;
        RECT  0 21.696 0.192 21.72 ;
    END
  END o0[99]
  PIN o0[9]
    DIRECTION OUTPUT ;
    USE SIGNAL ;
    PORT
      LAYER M4 ;
        RECT  0 6.096 0.192 6.12 ;
    END
  END o0[9]
  PIN o1[0]
    DIRECTION OUTPUT ;
    USE SIGNAL ;
    PORT
      LAYER M4 ;
        RECT  0 28.272 0.192 28.296 ;
    END
  END o1[0]
  PIN o1[100]
    DIRECTION OUTPUT ;
    USE SIGNAL ;
    PORT
      LAYER M4 ;
        RECT  0 45.648 0.192 45.672 ;
    END
  END o1[100]
  PIN o1[101]
    DIRECTION OUTPUT ;
    USE SIGNAL ;
    PORT
      LAYER M4 ;
        RECT  0 45.792 0.192 45.816 ;
    END
  END o1[101]
  PIN o1[102]
    DIRECTION OUTPUT ;
    USE SIGNAL ;
    PORT
      LAYER M4 ;
        RECT  0 45.984 0.192 46.008 ;
    END
  END o1[102]
  PIN o1[103]
    DIRECTION OUTPUT ;
    USE SIGNAL ;
    PORT
      LAYER M4 ;
        RECT  0 46.176 0.192 46.2 ;
    END
  END o1[103]
  PIN o1[104]
    DIRECTION OUTPUT ;
    USE SIGNAL ;
    PORT
      LAYER M4 ;
        RECT  0 46.32 0.192 46.344 ;
    END
  END o1[104]
  PIN o1[105]
    DIRECTION OUTPUT ;
    USE SIGNAL ;
    PORT
      LAYER M4 ;
        RECT  0 46.512 0.192 46.536 ;
    END
  END o1[105]
  PIN o1[106]
    DIRECTION OUTPUT ;
    USE SIGNAL ;
    PORT
      LAYER M4 ;
        RECT  0 46.656 0.192 46.68 ;
    END
  END o1[106]
  PIN o1[107]
    DIRECTION OUTPUT ;
    USE SIGNAL ;
    PORT
      LAYER M4 ;
        RECT  0 46.848 0.192 46.872 ;
    END
  END o1[107]
  PIN o1[108]
    DIRECTION OUTPUT ;
    USE SIGNAL ;
    PORT
      LAYER M4 ;
        RECT  0 46.992 0.192 47.016 ;
    END
  END o1[108]
  PIN o1[109]
    DIRECTION OUTPUT ;
    USE SIGNAL ;
    PORT
      LAYER M4 ;
        RECT  0 47.184 0.192 47.208 ;
    END
  END o1[109]
  PIN o1[10]
    DIRECTION OUTPUT ;
    USE SIGNAL ;
    PORT
      LAYER M4 ;
        RECT  0 30 0.192 30.024 ;
    END
  END o1[10]
  PIN o1[110]
    DIRECTION OUTPUT ;
    USE SIGNAL ;
    PORT
      LAYER M4 ;
        RECT  0 47.376 0.192 47.4 ;
    END
  END o1[110]
  PIN o1[111]
    DIRECTION OUTPUT ;
    USE SIGNAL ;
    PORT
      LAYER M4 ;
        RECT  0 47.52 0.192 47.544 ;
    END
  END o1[111]
  PIN o1[112]
    DIRECTION OUTPUT ;
    USE SIGNAL ;
    PORT
      LAYER M4 ;
        RECT  0 47.712 0.192 47.736 ;
    END
  END o1[112]
  PIN o1[113]
    DIRECTION OUTPUT ;
    USE SIGNAL ;
    PORT
      LAYER M4 ;
        RECT  0 47.856 0.192 47.88 ;
    END
  END o1[113]
  PIN o1[114]
    DIRECTION OUTPUT ;
    USE SIGNAL ;
    PORT
      LAYER M4 ;
        RECT  0 48.048 0.192 48.072 ;
    END
  END o1[114]
  PIN o1[115]
    DIRECTION OUTPUT ;
    USE SIGNAL ;
    PORT
      LAYER M4 ;
        RECT  0 48.24 0.192 48.264 ;
    END
  END o1[115]
  PIN o1[116]
    DIRECTION OUTPUT ;
    USE SIGNAL ;
    PORT
      LAYER M4 ;
        RECT  0 48.384 0.192 48.408 ;
    END
  END o1[116]
  PIN o1[117]
    DIRECTION OUTPUT ;
    USE SIGNAL ;
    PORT
      LAYER M4 ;
        RECT  0 48.576 0.192 48.6 ;
    END
  END o1[117]
  PIN o1[118]
    DIRECTION OUTPUT ;
    USE SIGNAL ;
    PORT
      LAYER M4 ;
        RECT  0 48.72 0.192 48.744 ;
    END
  END o1[118]
  PIN o1[119]
    DIRECTION OUTPUT ;
    USE SIGNAL ;
    PORT
      LAYER M4 ;
        RECT  0 48.912 0.192 48.936 ;
    END
  END o1[119]
  PIN o1[11]
    DIRECTION OUTPUT ;
    USE SIGNAL ;
    PORT
      LAYER M4 ;
        RECT  0 30.192 0.192 30.216 ;
    END
  END o1[11]
  PIN o1[120]
    DIRECTION OUTPUT ;
    USE SIGNAL ;
    PORT
      LAYER M4 ;
        RECT  0 49.056 0.192 49.08 ;
    END
  END o1[120]
  PIN o1[121]
    DIRECTION OUTPUT ;
    USE SIGNAL ;
    PORT
      LAYER M4 ;
        RECT  0 49.248 0.192 49.272 ;
    END
  END o1[121]
  PIN o1[122]
    DIRECTION OUTPUT ;
    USE SIGNAL ;
    PORT
      LAYER M4 ;
        RECT  0 49.44 0.192 49.464 ;
    END
  END o1[122]
  PIN o1[123]
    DIRECTION OUTPUT ;
    USE SIGNAL ;
    PORT
      LAYER M4 ;
        RECT  0 49.584 0.192 49.608 ;
    END
  END o1[123]
  PIN o1[124]
    DIRECTION OUTPUT ;
    USE SIGNAL ;
    PORT
      LAYER M4 ;
        RECT  0 49.776 0.192 49.8 ;
    END
  END o1[124]
  PIN o1[125]
    DIRECTION OUTPUT ;
    USE SIGNAL ;
    PORT
      LAYER M4 ;
        RECT  0 49.92 0.192 49.944 ;
    END
  END o1[125]
  PIN o1[126]
    DIRECTION OUTPUT ;
    USE SIGNAL ;
    PORT
      LAYER M4 ;
        RECT  0 50.112 0.192 50.136 ;
    END
  END o1[126]
  PIN o1[127]
    DIRECTION OUTPUT ;
    USE SIGNAL ;
    PORT
      LAYER M4 ;
        RECT  0 50.256 0.192 50.28 ;
    END
  END o1[127]
  PIN o1[128]
    DIRECTION OUTPUT ;
    USE SIGNAL ;
    PORT
      LAYER M4 ;
        RECT  0 50.448 0.192 50.472 ;
    END
  END o1[128]
  PIN o1[129]
    DIRECTION OUTPUT ;
    USE SIGNAL ;
    PORT
      LAYER M4 ;
        RECT  0 50.64 0.192 50.664 ;
    END
  END o1[129]
  PIN o1[12]
    DIRECTION OUTPUT ;
    USE SIGNAL ;
    PORT
      LAYER M4 ;
        RECT  0 30.336 0.192 30.36 ;
    END
  END o1[12]
  PIN o1[130]
    DIRECTION OUTPUT ;
    USE SIGNAL ;
    PORT
      LAYER M4 ;
        RECT  0 50.784 0.192 50.808 ;
    END
  END o1[130]
  PIN o1[131]
    DIRECTION OUTPUT ;
    USE SIGNAL ;
    PORT
      LAYER M4 ;
        RECT  0 50.976 0.192 51 ;
    END
  END o1[131]
  PIN o1[132]
    DIRECTION OUTPUT ;
    USE SIGNAL ;
    PORT
      LAYER M4 ;
        RECT  0 51.12 0.192 51.144 ;
    END
  END o1[132]
  PIN o1[133]
    DIRECTION OUTPUT ;
    USE SIGNAL ;
    PORT
      LAYER M4 ;
        RECT  0 51.312 0.192 51.336 ;
    END
  END o1[133]
  PIN o1[134]
    DIRECTION OUTPUT ;
    USE SIGNAL ;
    PORT
      LAYER M4 ;
        RECT  0 51.504 0.192 51.528 ;
    END
  END o1[134]
  PIN o1[135]
    DIRECTION OUTPUT ;
    USE SIGNAL ;
    PORT
      LAYER M4 ;
        RECT  0 51.648 0.192 51.672 ;
    END
  END o1[135]
  PIN o1[13]
    DIRECTION OUTPUT ;
    USE SIGNAL ;
    PORT
      LAYER M4 ;
        RECT  0 30.528 0.192 30.552 ;
    END
  END o1[13]
  PIN o1[14]
    DIRECTION OUTPUT ;
    USE SIGNAL ;
    PORT
      LAYER M4 ;
        RECT  0 30.72 0.192 30.744 ;
    END
  END o1[14]
  PIN o1[15]
    DIRECTION OUTPUT ;
    USE SIGNAL ;
    PORT
      LAYER M4 ;
        RECT  0 30.864 0.192 30.888 ;
    END
  END o1[15]
  PIN o1[16]
    DIRECTION OUTPUT ;
    USE SIGNAL ;
    PORT
      LAYER M4 ;
        RECT  0 31.056 0.192 31.08 ;
    END
  END o1[16]
  PIN o1[17]
    DIRECTION OUTPUT ;
    USE SIGNAL ;
    PORT
      LAYER M4 ;
        RECT  0 31.2 0.192 31.224 ;
    END
  END o1[17]
  PIN o1[18]
    DIRECTION OUTPUT ;
    USE SIGNAL ;
    PORT
      LAYER M4 ;
        RECT  0 31.392 0.192 31.416 ;
    END
  END o1[18]
  PIN o1[19]
    DIRECTION OUTPUT ;
    USE SIGNAL ;
    PORT
      LAYER M4 ;
        RECT  0 31.536 0.192 31.56 ;
    END
  END o1[19]
  PIN o1[1]
    DIRECTION OUTPUT ;
    USE SIGNAL ;
    PORT
      LAYER M4 ;
        RECT  0 28.464 0.192 28.488 ;
    END
  END o1[1]
  PIN o1[20]
    DIRECTION OUTPUT ;
    USE SIGNAL ;
    PORT
      LAYER M4 ;
        RECT  0 31.728 0.192 31.752 ;
    END
  END o1[20]
  PIN o1[21]
    DIRECTION OUTPUT ;
    USE SIGNAL ;
    PORT
      LAYER M4 ;
        RECT  0 31.92 0.192 31.944 ;
    END
  END o1[21]
  PIN o1[22]
    DIRECTION OUTPUT ;
    USE SIGNAL ;
    PORT
      LAYER M4 ;
        RECT  0 32.064 0.192 32.088 ;
    END
  END o1[22]
  PIN o1[23]
    DIRECTION OUTPUT ;
    USE SIGNAL ;
    PORT
      LAYER M4 ;
        RECT  0 32.256 0.192 32.28 ;
    END
  END o1[23]
  PIN o1[24]
    DIRECTION OUTPUT ;
    USE SIGNAL ;
    PORT
      LAYER M4 ;
        RECT  0 32.4 0.192 32.424 ;
    END
  END o1[24]
  PIN o1[25]
    DIRECTION OUTPUT ;
    USE SIGNAL ;
    PORT
      LAYER M4 ;
        RECT  0 32.592 0.192 32.616 ;
    END
  END o1[25]
  PIN o1[26]
    DIRECTION OUTPUT ;
    USE SIGNAL ;
    PORT
      LAYER M4 ;
        RECT  0 32.736 0.192 32.76 ;
    END
  END o1[26]
  PIN o1[27]
    DIRECTION OUTPUT ;
    USE SIGNAL ;
    PORT
      LAYER M4 ;
        RECT  0 32.928 0.192 32.952 ;
    END
  END o1[27]
  PIN o1[28]
    DIRECTION OUTPUT ;
    USE SIGNAL ;
    PORT
      LAYER M4 ;
        RECT  0 33.12 0.192 33.144 ;
    END
  END o1[28]
  PIN o1[29]
    DIRECTION OUTPUT ;
    USE SIGNAL ;
    PORT
      LAYER M4 ;
        RECT  0 33.264 0.192 33.288 ;
    END
  END o1[29]
  PIN o1[2]
    DIRECTION OUTPUT ;
    USE SIGNAL ;
    PORT
      LAYER M4 ;
        RECT  0 28.656 0.192 28.68 ;
    END
  END o1[2]
  PIN o1[30]
    DIRECTION OUTPUT ;
    USE SIGNAL ;
    PORT
      LAYER M4 ;
        RECT  0 33.456 0.192 33.48 ;
    END
  END o1[30]
  PIN o1[31]
    DIRECTION OUTPUT ;
    USE SIGNAL ;
    PORT
      LAYER M4 ;
        RECT  0 33.6 0.192 33.624 ;
    END
  END o1[31]
  PIN o1[32]
    DIRECTION OUTPUT ;
    USE SIGNAL ;
    PORT
      LAYER M4 ;
        RECT  0 33.792 0.192 33.816 ;
    END
  END o1[32]
  PIN o1[33]
    DIRECTION OUTPUT ;
    USE SIGNAL ;
    PORT
      LAYER M4 ;
        RECT  0 33.984 0.192 34.008 ;
    END
  END o1[33]
  PIN o1[34]
    DIRECTION OUTPUT ;
    USE SIGNAL ;
    PORT
      LAYER M4 ;
        RECT  0 34.128 0.192 34.152 ;
    END
  END o1[34]
  PIN o1[35]
    DIRECTION OUTPUT ;
    USE SIGNAL ;
    PORT
      LAYER M4 ;
        RECT  0 34.32 0.192 34.344 ;
    END
  END o1[35]
  PIN o1[36]
    DIRECTION OUTPUT ;
    USE SIGNAL ;
    PORT
      LAYER M4 ;
        RECT  0 34.464 0.192 34.488 ;
    END
  END o1[36]
  PIN o1[37]
    DIRECTION OUTPUT ;
    USE SIGNAL ;
    PORT
      LAYER M4 ;
        RECT  0 34.656 0.192 34.68 ;
    END
  END o1[37]
  PIN o1[38]
    DIRECTION OUTPUT ;
    USE SIGNAL ;
    PORT
      LAYER M4 ;
        RECT  0 34.8 0.192 34.824 ;
    END
  END o1[38]
  PIN o1[39]
    DIRECTION OUTPUT ;
    USE SIGNAL ;
    PORT
      LAYER M4 ;
        RECT  0 34.992 0.192 35.016 ;
    END
  END o1[39]
  PIN o1[3]
    DIRECTION OUTPUT ;
    USE SIGNAL ;
    PORT
      LAYER M4 ;
        RECT  0 28.8 0.192 28.824 ;
    END
  END o1[3]
  PIN o1[40]
    DIRECTION OUTPUT ;
    USE SIGNAL ;
    PORT
      LAYER M4 ;
        RECT  0 35.184 0.192 35.208 ;
    END
  END o1[40]
  PIN o1[41]
    DIRECTION OUTPUT ;
    USE SIGNAL ;
    PORT
      LAYER M4 ;
        RECT  0 35.328 0.192 35.352 ;
    END
  END o1[41]
  PIN o1[42]
    DIRECTION OUTPUT ;
    USE SIGNAL ;
    PORT
      LAYER M4 ;
        RECT  0 35.52 0.192 35.544 ;
    END
  END o1[42]
  PIN o1[43]
    DIRECTION OUTPUT ;
    USE SIGNAL ;
    PORT
      LAYER M4 ;
        RECT  0 35.664 0.192 35.688 ;
    END
  END o1[43]
  PIN o1[44]
    DIRECTION OUTPUT ;
    USE SIGNAL ;
    PORT
      LAYER M4 ;
        RECT  0 35.856 0.192 35.88 ;
    END
  END o1[44]
  PIN o1[45]
    DIRECTION OUTPUT ;
    USE SIGNAL ;
    PORT
      LAYER M4 ;
        RECT  0 36 0.192 36.024 ;
    END
  END o1[45]
  PIN o1[46]
    DIRECTION OUTPUT ;
    USE SIGNAL ;
    PORT
      LAYER M4 ;
        RECT  0 36.192 0.192 36.216 ;
    END
  END o1[46]
  PIN o1[47]
    DIRECTION OUTPUT ;
    USE SIGNAL ;
    PORT
      LAYER M4 ;
        RECT  0 36.384 0.192 36.408 ;
    END
  END o1[47]
  PIN o1[48]
    DIRECTION OUTPUT ;
    USE SIGNAL ;
    PORT
      LAYER M4 ;
        RECT  0 36.528 0.192 36.552 ;
    END
  END o1[48]
  PIN o1[49]
    DIRECTION OUTPUT ;
    USE SIGNAL ;
    PORT
      LAYER M4 ;
        RECT  0 36.72 0.192 36.744 ;
    END
  END o1[49]
  PIN o1[4]
    DIRECTION OUTPUT ;
    USE SIGNAL ;
    PORT
      LAYER M4 ;
        RECT  0 28.992 0.192 29.016 ;
    END
  END o1[4]
  PIN o1[50]
    DIRECTION OUTPUT ;
    USE SIGNAL ;
    PORT
      LAYER M4 ;
        RECT  0 36.864 0.192 36.888 ;
    END
  END o1[50]
  PIN o1[51]
    DIRECTION OUTPUT ;
    USE SIGNAL ;
    PORT
      LAYER M4 ;
        RECT  0 37.056 0.192 37.08 ;
    END
  END o1[51]
  PIN o1[52]
    DIRECTION OUTPUT ;
    USE SIGNAL ;
    PORT
      LAYER M4 ;
        RECT  0 37.2 0.192 37.224 ;
    END
  END o1[52]
  PIN o1[53]
    DIRECTION OUTPUT ;
    USE SIGNAL ;
    PORT
      LAYER M4 ;
        RECT  0 37.392 0.192 37.416 ;
    END
  END o1[53]
  PIN o1[54]
    DIRECTION OUTPUT ;
    USE SIGNAL ;
    PORT
      LAYER M4 ;
        RECT  0 37.584 0.192 37.608 ;
    END
  END o1[54]
  PIN o1[55]
    DIRECTION OUTPUT ;
    USE SIGNAL ;
    PORT
      LAYER M4 ;
        RECT  0 37.728 0.192 37.752 ;
    END
  END o1[55]
  PIN o1[56]
    DIRECTION OUTPUT ;
    USE SIGNAL ;
    PORT
      LAYER M4 ;
        RECT  0 37.92 0.192 37.944 ;
    END
  END o1[56]
  PIN o1[57]
    DIRECTION OUTPUT ;
    USE SIGNAL ;
    PORT
      LAYER M4 ;
        RECT  0 38.064 0.192 38.088 ;
    END
  END o1[57]
  PIN o1[58]
    DIRECTION OUTPUT ;
    USE SIGNAL ;
    PORT
      LAYER M4 ;
        RECT  0 38.256 0.192 38.28 ;
    END
  END o1[58]
  PIN o1[59]
    DIRECTION OUTPUT ;
    USE SIGNAL ;
    PORT
      LAYER M4 ;
        RECT  0 38.448 0.192 38.472 ;
    END
  END o1[59]
  PIN o1[5]
    DIRECTION OUTPUT ;
    USE SIGNAL ;
    PORT
      LAYER M4 ;
        RECT  0 29.136 0.192 29.16 ;
    END
  END o1[5]
  PIN o1[60]
    DIRECTION OUTPUT ;
    USE SIGNAL ;
    PORT
      LAYER M4 ;
        RECT  0 38.592 0.192 38.616 ;
    END
  END o1[60]
  PIN o1[61]
    DIRECTION OUTPUT ;
    USE SIGNAL ;
    PORT
      LAYER M4 ;
        RECT  0 38.784 0.192 38.808 ;
    END
  END o1[61]
  PIN o1[62]
    DIRECTION OUTPUT ;
    USE SIGNAL ;
    PORT
      LAYER M4 ;
        RECT  0 38.928 0.192 38.952 ;
    END
  END o1[62]
  PIN o1[63]
    DIRECTION OUTPUT ;
    USE SIGNAL ;
    PORT
      LAYER M4 ;
        RECT  0 39.12 0.192 39.144 ;
    END
  END o1[63]
  PIN o1[64]
    DIRECTION OUTPUT ;
    USE SIGNAL ;
    PORT
      LAYER M4 ;
        RECT  0 39.264 0.192 39.288 ;
    END
  END o1[64]
  PIN o1[65]
    DIRECTION OUTPUT ;
    USE SIGNAL ;
    PORT
      LAYER M4 ;
        RECT  0 39.456 0.192 39.48 ;
    END
  END o1[65]
  PIN o1[66]
    DIRECTION OUTPUT ;
    USE SIGNAL ;
    PORT
      LAYER M4 ;
        RECT  0 39.648 0.192 39.672 ;
    END
  END o1[66]
  PIN o1[67]
    DIRECTION OUTPUT ;
    USE SIGNAL ;
    PORT
      LAYER M4 ;
        RECT  0 39.792 0.192 39.816 ;
    END
  END o1[67]
  PIN o1[68]
    DIRECTION OUTPUT ;
    USE SIGNAL ;
    PORT
      LAYER M4 ;
        RECT  0 40.128 0.192 40.152 ;
    END
  END o1[68]
  PIN o1[69]
    DIRECTION OUTPUT ;
    USE SIGNAL ;
    PORT
      LAYER M4 ;
        RECT  0 40.32 0.192 40.344 ;
    END
  END o1[69]
  PIN o1[6]
    DIRECTION OUTPUT ;
    USE SIGNAL ;
    PORT
      LAYER M4 ;
        RECT  0 29.328 0.192 29.352 ;
    END
  END o1[6]
  PIN o1[70]
    DIRECTION OUTPUT ;
    USE SIGNAL ;
    PORT
      LAYER M4 ;
        RECT  0 40.464 0.192 40.488 ;
    END
  END o1[70]
  PIN o1[71]
    DIRECTION OUTPUT ;
    USE SIGNAL ;
    PORT
      LAYER M4 ;
        RECT  0 40.656 0.192 40.68 ;
    END
  END o1[71]
  PIN o1[72]
    DIRECTION OUTPUT ;
    USE SIGNAL ;
    PORT
      LAYER M4 ;
        RECT  0 40.848 0.192 40.872 ;
    END
  END o1[72]
  PIN o1[73]
    DIRECTION OUTPUT ;
    USE SIGNAL ;
    PORT
      LAYER M4 ;
        RECT  0 40.992 0.192 41.016 ;
    END
  END o1[73]
  PIN o1[74]
    DIRECTION OUTPUT ;
    USE SIGNAL ;
    PORT
      LAYER M4 ;
        RECT  0 41.184 0.192 41.208 ;
    END
  END o1[74]
  PIN o1[75]
    DIRECTION OUTPUT ;
    USE SIGNAL ;
    PORT
      LAYER M4 ;
        RECT  0 41.328 0.192 41.352 ;
    END
  END o1[75]
  PIN o1[76]
    DIRECTION OUTPUT ;
    USE SIGNAL ;
    PORT
      LAYER M4 ;
        RECT  0 41.52 0.192 41.544 ;
    END
  END o1[76]
  PIN o1[77]
    DIRECTION OUTPUT ;
    USE SIGNAL ;
    PORT
      LAYER M4 ;
        RECT  0 41.712 0.192 41.736 ;
    END
  END o1[77]
  PIN o1[78]
    DIRECTION OUTPUT ;
    USE SIGNAL ;
    PORT
      LAYER M4 ;
        RECT  0 41.856 0.192 41.88 ;
    END
  END o1[78]
  PIN o1[79]
    DIRECTION OUTPUT ;
    USE SIGNAL ;
    PORT
      LAYER M4 ;
        RECT  0 42.048 0.192 42.072 ;
    END
  END o1[79]
  PIN o1[7]
    DIRECTION OUTPUT ;
    USE SIGNAL ;
    PORT
      LAYER M4 ;
        RECT  0 29.472 0.192 29.496 ;
    END
  END o1[7]
  PIN o1[80]
    DIRECTION OUTPUT ;
    USE SIGNAL ;
    PORT
      LAYER M4 ;
        RECT  0 42.192 0.192 42.216 ;
    END
  END o1[80]
  PIN o1[81]
    DIRECTION OUTPUT ;
    USE SIGNAL ;
    PORT
      LAYER M4 ;
        RECT  0 42.384 0.192 42.408 ;
    END
  END o1[81]
  PIN o1[82]
    DIRECTION OUTPUT ;
    USE SIGNAL ;
    PORT
      LAYER M4 ;
        RECT  0 42.528 0.192 42.552 ;
    END
  END o1[82]
  PIN o1[83]
    DIRECTION OUTPUT ;
    USE SIGNAL ;
    PORT
      LAYER M4 ;
        RECT  0 42.72 0.192 42.744 ;
    END
  END o1[83]
  PIN o1[84]
    DIRECTION OUTPUT ;
    USE SIGNAL ;
    PORT
      LAYER M4 ;
        RECT  0 42.912 0.192 42.936 ;
    END
  END o1[84]
  PIN o1[85]
    DIRECTION OUTPUT ;
    USE SIGNAL ;
    PORT
      LAYER M4 ;
        RECT  0 43.056 0.192 43.08 ;
    END
  END o1[85]
  PIN o1[86]
    DIRECTION OUTPUT ;
    USE SIGNAL ;
    PORT
      LAYER M4 ;
        RECT  0 43.248 0.192 43.272 ;
    END
  END o1[86]
  PIN o1[87]
    DIRECTION OUTPUT ;
    USE SIGNAL ;
    PORT
      LAYER M4 ;
        RECT  0 43.392 0.192 43.416 ;
    END
  END o1[87]
  PIN o1[88]
    DIRECTION OUTPUT ;
    USE SIGNAL ;
    PORT
      LAYER M4 ;
        RECT  0 43.584 0.192 43.608 ;
    END
  END o1[88]
  PIN o1[89]
    DIRECTION OUTPUT ;
    USE SIGNAL ;
    PORT
      LAYER M4 ;
        RECT  0 43.728 0.192 43.752 ;
    END
  END o1[89]
  PIN o1[8]
    DIRECTION OUTPUT ;
    USE SIGNAL ;
    PORT
      LAYER M4 ;
        RECT  0 29.664 0.192 29.688 ;
    END
  END o1[8]
  PIN o1[90]
    DIRECTION OUTPUT ;
    USE SIGNAL ;
    PORT
      LAYER M4 ;
        RECT  0 43.92 0.192 43.944 ;
    END
  END o1[90]
  PIN o1[91]
    DIRECTION OUTPUT ;
    USE SIGNAL ;
    PORT
      LAYER M4 ;
        RECT  0 44.112 0.192 44.136 ;
    END
  END o1[91]
  PIN o1[92]
    DIRECTION OUTPUT ;
    USE SIGNAL ;
    PORT
      LAYER M4 ;
        RECT  0 44.256 0.192 44.28 ;
    END
  END o1[92]
  PIN o1[93]
    DIRECTION OUTPUT ;
    USE SIGNAL ;
    PORT
      LAYER M4 ;
        RECT  0 44.448 0.192 44.472 ;
    END
  END o1[93]
  PIN o1[94]
    DIRECTION OUTPUT ;
    USE SIGNAL ;
    PORT
      LAYER M4 ;
        RECT  0 44.592 0.192 44.616 ;
    END
  END o1[94]
  PIN o1[95]
    DIRECTION OUTPUT ;
    USE SIGNAL ;
    PORT
      LAYER M4 ;
        RECT  0 44.784 0.192 44.808 ;
    END
  END o1[95]
  PIN o1[96]
    DIRECTION OUTPUT ;
    USE SIGNAL ;
    PORT
      LAYER M4 ;
        RECT  0 44.976 0.192 45 ;
    END
  END o1[96]
  PIN o1[97]
    DIRECTION OUTPUT ;
    USE SIGNAL ;
    PORT
      LAYER M4 ;
        RECT  0 45.12 0.192 45.144 ;
    END
  END o1[97]
  PIN o1[98]
    DIRECTION OUTPUT ;
    USE SIGNAL ;
    PORT
      LAYER M4 ;
        RECT  0 45.312 0.192 45.336 ;
    END
  END o1[98]
  PIN o1[99]
    DIRECTION OUTPUT ;
    USE SIGNAL ;
    PORT
      LAYER M4 ;
        RECT  0 45.456 0.192 45.48 ;
    END
  END o1[99]
  PIN o1[9]
    DIRECTION OUTPUT ;
    USE SIGNAL ;
    PORT
      LAYER M4 ;
        RECT  0 29.856 0.192 29.88 ;
    END
  END o1[9]
  PIN o2[0]
    DIRECTION OUTPUT ;
    USE SIGNAL ;
    PORT
      LAYER M4 ;
        RECT  21.408 28.272 21.6 28.296 ;
    END
  END o2[0]
  PIN o2[100]
    DIRECTION OUTPUT ;
    USE SIGNAL ;
    PORT
      LAYER M4 ;
        RECT  21.408 45.648 21.6 45.672 ;
    END
  END o2[100]
  PIN o2[101]
    DIRECTION OUTPUT ;
    USE SIGNAL ;
    PORT
      LAYER M4 ;
        RECT  21.408 45.792 21.6 45.816 ;
    END
  END o2[101]
  PIN o2[102]
    DIRECTION OUTPUT ;
    USE SIGNAL ;
    PORT
      LAYER M4 ;
        RECT  21.408 45.984 21.6 46.008 ;
    END
  END o2[102]
  PIN o2[103]
    DIRECTION OUTPUT ;
    USE SIGNAL ;
    PORT
      LAYER M4 ;
        RECT  21.408 46.176 21.6 46.2 ;
    END
  END o2[103]
  PIN o2[104]
    DIRECTION OUTPUT ;
    USE SIGNAL ;
    PORT
      LAYER M4 ;
        RECT  21.408 46.32 21.6 46.344 ;
    END
  END o2[104]
  PIN o2[105]
    DIRECTION OUTPUT ;
    USE SIGNAL ;
    PORT
      LAYER M4 ;
        RECT  21.408 46.512 21.6 46.536 ;
    END
  END o2[105]
  PIN o2[106]
    DIRECTION OUTPUT ;
    USE SIGNAL ;
    PORT
      LAYER M4 ;
        RECT  21.408 46.656 21.6 46.68 ;
    END
  END o2[106]
  PIN o2[107]
    DIRECTION OUTPUT ;
    USE SIGNAL ;
    PORT
      LAYER M4 ;
        RECT  21.408 46.848 21.6 46.872 ;
    END
  END o2[107]
  PIN o2[108]
    DIRECTION OUTPUT ;
    USE SIGNAL ;
    PORT
      LAYER M4 ;
        RECT  21.408 46.992 21.6 47.016 ;
    END
  END o2[108]
  PIN o2[109]
    DIRECTION OUTPUT ;
    USE SIGNAL ;
    PORT
      LAYER M4 ;
        RECT  21.408 47.184 21.6 47.208 ;
    END
  END o2[109]
  PIN o2[10]
    DIRECTION OUTPUT ;
    USE SIGNAL ;
    PORT
      LAYER M4 ;
        RECT  21.408 30 21.6 30.024 ;
    END
  END o2[10]
  PIN o2[110]
    DIRECTION OUTPUT ;
    USE SIGNAL ;
    PORT
      LAYER M4 ;
        RECT  21.408 47.376 21.6 47.4 ;
    END
  END o2[110]
  PIN o2[111]
    DIRECTION OUTPUT ;
    USE SIGNAL ;
    PORT
      LAYER M4 ;
        RECT  21.408 47.52 21.6 47.544 ;
    END
  END o2[111]
  PIN o2[112]
    DIRECTION OUTPUT ;
    USE SIGNAL ;
    PORT
      LAYER M4 ;
        RECT  21.408 47.712 21.6 47.736 ;
    END
  END o2[112]
  PIN o2[113]
    DIRECTION OUTPUT ;
    USE SIGNAL ;
    PORT
      LAYER M4 ;
        RECT  21.408 47.856 21.6 47.88 ;
    END
  END o2[113]
  PIN o2[114]
    DIRECTION OUTPUT ;
    USE SIGNAL ;
    PORT
      LAYER M4 ;
        RECT  21.408 48.048 21.6 48.072 ;
    END
  END o2[114]
  PIN o2[115]
    DIRECTION OUTPUT ;
    USE SIGNAL ;
    PORT
      LAYER M4 ;
        RECT  21.408 48.24 21.6 48.264 ;
    END
  END o2[115]
  PIN o2[116]
    DIRECTION OUTPUT ;
    USE SIGNAL ;
    PORT
      LAYER M4 ;
        RECT  21.408 48.384 21.6 48.408 ;
    END
  END o2[116]
  PIN o2[117]
    DIRECTION OUTPUT ;
    USE SIGNAL ;
    PORT
      LAYER M4 ;
        RECT  21.408 48.576 21.6 48.6 ;
    END
  END o2[117]
  PIN o2[118]
    DIRECTION OUTPUT ;
    USE SIGNAL ;
    PORT
      LAYER M4 ;
        RECT  21.408 48.72 21.6 48.744 ;
    END
  END o2[118]
  PIN o2[119]
    DIRECTION OUTPUT ;
    USE SIGNAL ;
    PORT
      LAYER M4 ;
        RECT  21.408 48.912 21.6 48.936 ;
    END
  END o2[119]
  PIN o2[11]
    DIRECTION OUTPUT ;
    USE SIGNAL ;
    PORT
      LAYER M4 ;
        RECT  21.408 30.192 21.6 30.216 ;
    END
  END o2[11]
  PIN o2[120]
    DIRECTION OUTPUT ;
    USE SIGNAL ;
    PORT
      LAYER M4 ;
        RECT  21.408 49.056 21.6 49.08 ;
    END
  END o2[120]
  PIN o2[121]
    DIRECTION OUTPUT ;
    USE SIGNAL ;
    PORT
      LAYER M4 ;
        RECT  21.408 49.248 21.6 49.272 ;
    END
  END o2[121]
  PIN o2[122]
    DIRECTION OUTPUT ;
    USE SIGNAL ;
    PORT
      LAYER M4 ;
        RECT  21.408 49.44 21.6 49.464 ;
    END
  END o2[122]
  PIN o2[123]
    DIRECTION OUTPUT ;
    USE SIGNAL ;
    PORT
      LAYER M4 ;
        RECT  21.408 49.584 21.6 49.608 ;
    END
  END o2[123]
  PIN o2[124]
    DIRECTION OUTPUT ;
    USE SIGNAL ;
    PORT
      LAYER M4 ;
        RECT  21.408 49.776 21.6 49.8 ;
    END
  END o2[124]
  PIN o2[125]
    DIRECTION OUTPUT ;
    USE SIGNAL ;
    PORT
      LAYER M4 ;
        RECT  21.408 49.92 21.6 49.944 ;
    END
  END o2[125]
  PIN o2[126]
    DIRECTION OUTPUT ;
    USE SIGNAL ;
    PORT
      LAYER M4 ;
        RECT  21.408 50.112 21.6 50.136 ;
    END
  END o2[126]
  PIN o2[127]
    DIRECTION OUTPUT ;
    USE SIGNAL ;
    PORT
      LAYER M4 ;
        RECT  21.408 50.256 21.6 50.28 ;
    END
  END o2[127]
  PIN o2[128]
    DIRECTION OUTPUT ;
    USE SIGNAL ;
    PORT
      LAYER M4 ;
        RECT  21.408 50.448 21.6 50.472 ;
    END
  END o2[128]
  PIN o2[129]
    DIRECTION OUTPUT ;
    USE SIGNAL ;
    PORT
      LAYER M4 ;
        RECT  21.408 50.64 21.6 50.664 ;
    END
  END o2[129]
  PIN o2[12]
    DIRECTION OUTPUT ;
    USE SIGNAL ;
    PORT
      LAYER M4 ;
        RECT  21.408 30.336 21.6 30.36 ;
    END
  END o2[12]
  PIN o2[130]
    DIRECTION OUTPUT ;
    USE SIGNAL ;
    PORT
      LAYER M4 ;
        RECT  21.408 50.784 21.6 50.808 ;
    END
  END o2[130]
  PIN o2[131]
    DIRECTION OUTPUT ;
    USE SIGNAL ;
    PORT
      LAYER M4 ;
        RECT  21.408 50.976 21.6 51 ;
    END
  END o2[131]
  PIN o2[132]
    DIRECTION OUTPUT ;
    USE SIGNAL ;
    PORT
      LAYER M4 ;
        RECT  21.408 51.12 21.6 51.144 ;
    END
  END o2[132]
  PIN o2[133]
    DIRECTION OUTPUT ;
    USE SIGNAL ;
    PORT
      LAYER M4 ;
        RECT  21.408 51.312 21.6 51.336 ;
    END
  END o2[133]
  PIN o2[134]
    DIRECTION OUTPUT ;
    USE SIGNAL ;
    PORT
      LAYER M4 ;
        RECT  21.408 51.504 21.6 51.528 ;
    END
  END o2[134]
  PIN o2[135]
    DIRECTION OUTPUT ;
    USE SIGNAL ;
    PORT
      LAYER M4 ;
        RECT  21.408 51.648 21.6 51.672 ;
    END
  END o2[135]
  PIN o2[13]
    DIRECTION OUTPUT ;
    USE SIGNAL ;
    PORT
      LAYER M4 ;
        RECT  21.408 30.528 21.6 30.552 ;
    END
  END o2[13]
  PIN o2[14]
    DIRECTION OUTPUT ;
    USE SIGNAL ;
    PORT
      LAYER M4 ;
        RECT  21.408 30.72 21.6 30.744 ;
    END
  END o2[14]
  PIN o2[15]
    DIRECTION OUTPUT ;
    USE SIGNAL ;
    PORT
      LAYER M4 ;
        RECT  21.408 30.864 21.6 30.888 ;
    END
  END o2[15]
  PIN o2[16]
    DIRECTION OUTPUT ;
    USE SIGNAL ;
    PORT
      LAYER M4 ;
        RECT  21.408 31.056 21.6 31.08 ;
    END
  END o2[16]
  PIN o2[17]
    DIRECTION OUTPUT ;
    USE SIGNAL ;
    PORT
      LAYER M4 ;
        RECT  21.408 31.2 21.6 31.224 ;
    END
  END o2[17]
  PIN o2[18]
    DIRECTION OUTPUT ;
    USE SIGNAL ;
    PORT
      LAYER M4 ;
        RECT  21.408 31.392 21.6 31.416 ;
    END
  END o2[18]
  PIN o2[19]
    DIRECTION OUTPUT ;
    USE SIGNAL ;
    PORT
      LAYER M4 ;
        RECT  21.408 31.536 21.6 31.56 ;
    END
  END o2[19]
  PIN o2[1]
    DIRECTION OUTPUT ;
    USE SIGNAL ;
    PORT
      LAYER M4 ;
        RECT  21.408 28.464 21.6 28.488 ;
    END
  END o2[1]
  PIN o2[20]
    DIRECTION OUTPUT ;
    USE SIGNAL ;
    PORT
      LAYER M4 ;
        RECT  21.408 31.728 21.6 31.752 ;
    END
  END o2[20]
  PIN o2[21]
    DIRECTION OUTPUT ;
    USE SIGNAL ;
    PORT
      LAYER M4 ;
        RECT  21.408 31.92 21.6 31.944 ;
    END
  END o2[21]
  PIN o2[22]
    DIRECTION OUTPUT ;
    USE SIGNAL ;
    PORT
      LAYER M4 ;
        RECT  21.408 32.064 21.6 32.088 ;
    END
  END o2[22]
  PIN o2[23]
    DIRECTION OUTPUT ;
    USE SIGNAL ;
    PORT
      LAYER M4 ;
        RECT  21.408 32.256 21.6 32.28 ;
    END
  END o2[23]
  PIN o2[24]
    DIRECTION OUTPUT ;
    USE SIGNAL ;
    PORT
      LAYER M4 ;
        RECT  21.408 32.4 21.6 32.424 ;
    END
  END o2[24]
  PIN o2[25]
    DIRECTION OUTPUT ;
    USE SIGNAL ;
    PORT
      LAYER M4 ;
        RECT  21.408 32.592 21.6 32.616 ;
    END
  END o2[25]
  PIN o2[26]
    DIRECTION OUTPUT ;
    USE SIGNAL ;
    PORT
      LAYER M4 ;
        RECT  21.408 32.736 21.6 32.76 ;
    END
  END o2[26]
  PIN o2[27]
    DIRECTION OUTPUT ;
    USE SIGNAL ;
    PORT
      LAYER M4 ;
        RECT  21.408 32.928 21.6 32.952 ;
    END
  END o2[27]
  PIN o2[28]
    DIRECTION OUTPUT ;
    USE SIGNAL ;
    PORT
      LAYER M4 ;
        RECT  21.408 33.12 21.6 33.144 ;
    END
  END o2[28]
  PIN o2[29]
    DIRECTION OUTPUT ;
    USE SIGNAL ;
    PORT
      LAYER M4 ;
        RECT  21.408 33.264 21.6 33.288 ;
    END
  END o2[29]
  PIN o2[2]
    DIRECTION OUTPUT ;
    USE SIGNAL ;
    PORT
      LAYER M4 ;
        RECT  21.408 28.656 21.6 28.68 ;
    END
  END o2[2]
  PIN o2[30]
    DIRECTION OUTPUT ;
    USE SIGNAL ;
    PORT
      LAYER M4 ;
        RECT  21.408 33.456 21.6 33.48 ;
    END
  END o2[30]
  PIN o2[31]
    DIRECTION OUTPUT ;
    USE SIGNAL ;
    PORT
      LAYER M4 ;
        RECT  21.408 33.6 21.6 33.624 ;
    END
  END o2[31]
  PIN o2[32]
    DIRECTION OUTPUT ;
    USE SIGNAL ;
    PORT
      LAYER M4 ;
        RECT  21.408 33.792 21.6 33.816 ;
    END
  END o2[32]
  PIN o2[33]
    DIRECTION OUTPUT ;
    USE SIGNAL ;
    PORT
      LAYER M4 ;
        RECT  21.408 33.984 21.6 34.008 ;
    END
  END o2[33]
  PIN o2[34]
    DIRECTION OUTPUT ;
    USE SIGNAL ;
    PORT
      LAYER M4 ;
        RECT  21.408 34.128 21.6 34.152 ;
    END
  END o2[34]
  PIN o2[35]
    DIRECTION OUTPUT ;
    USE SIGNAL ;
    PORT
      LAYER M4 ;
        RECT  21.408 34.32 21.6 34.344 ;
    END
  END o2[35]
  PIN o2[36]
    DIRECTION OUTPUT ;
    USE SIGNAL ;
    PORT
      LAYER M4 ;
        RECT  21.408 34.464 21.6 34.488 ;
    END
  END o2[36]
  PIN o2[37]
    DIRECTION OUTPUT ;
    USE SIGNAL ;
    PORT
      LAYER M4 ;
        RECT  21.408 34.656 21.6 34.68 ;
    END
  END o2[37]
  PIN o2[38]
    DIRECTION OUTPUT ;
    USE SIGNAL ;
    PORT
      LAYER M4 ;
        RECT  21.408 34.8 21.6 34.824 ;
    END
  END o2[38]
  PIN o2[39]
    DIRECTION OUTPUT ;
    USE SIGNAL ;
    PORT
      LAYER M4 ;
        RECT  21.408 34.992 21.6 35.016 ;
    END
  END o2[39]
  PIN o2[3]
    DIRECTION OUTPUT ;
    USE SIGNAL ;
    PORT
      LAYER M4 ;
        RECT  21.408 28.8 21.6 28.824 ;
    END
  END o2[3]
  PIN o2[40]
    DIRECTION OUTPUT ;
    USE SIGNAL ;
    PORT
      LAYER M4 ;
        RECT  21.408 35.184 21.6 35.208 ;
    END
  END o2[40]
  PIN o2[41]
    DIRECTION OUTPUT ;
    USE SIGNAL ;
    PORT
      LAYER M4 ;
        RECT  21.408 35.328 21.6 35.352 ;
    END
  END o2[41]
  PIN o2[42]
    DIRECTION OUTPUT ;
    USE SIGNAL ;
    PORT
      LAYER M4 ;
        RECT  21.408 35.52 21.6 35.544 ;
    END
  END o2[42]
  PIN o2[43]
    DIRECTION OUTPUT ;
    USE SIGNAL ;
    PORT
      LAYER M4 ;
        RECT  21.408 35.664 21.6 35.688 ;
    END
  END o2[43]
  PIN o2[44]
    DIRECTION OUTPUT ;
    USE SIGNAL ;
    PORT
      LAYER M4 ;
        RECT  21.408 35.856 21.6 35.88 ;
    END
  END o2[44]
  PIN o2[45]
    DIRECTION OUTPUT ;
    USE SIGNAL ;
    PORT
      LAYER M4 ;
        RECT  21.408 36 21.6 36.024 ;
    END
  END o2[45]
  PIN o2[46]
    DIRECTION OUTPUT ;
    USE SIGNAL ;
    PORT
      LAYER M4 ;
        RECT  21.408 36.192 21.6 36.216 ;
    END
  END o2[46]
  PIN o2[47]
    DIRECTION OUTPUT ;
    USE SIGNAL ;
    PORT
      LAYER M4 ;
        RECT  21.408 36.384 21.6 36.408 ;
    END
  END o2[47]
  PIN o2[48]
    DIRECTION OUTPUT ;
    USE SIGNAL ;
    PORT
      LAYER M4 ;
        RECT  21.408 36.528 21.6 36.552 ;
    END
  END o2[48]
  PIN o2[49]
    DIRECTION OUTPUT ;
    USE SIGNAL ;
    PORT
      LAYER M4 ;
        RECT  21.408 36.72 21.6 36.744 ;
    END
  END o2[49]
  PIN o2[4]
    DIRECTION OUTPUT ;
    USE SIGNAL ;
    PORT
      LAYER M4 ;
        RECT  21.408 28.992 21.6 29.016 ;
    END
  END o2[4]
  PIN o2[50]
    DIRECTION OUTPUT ;
    USE SIGNAL ;
    PORT
      LAYER M4 ;
        RECT  21.408 36.864 21.6 36.888 ;
    END
  END o2[50]
  PIN o2[51]
    DIRECTION OUTPUT ;
    USE SIGNAL ;
    PORT
      LAYER M4 ;
        RECT  21.408 37.056 21.6 37.08 ;
    END
  END o2[51]
  PIN o2[52]
    DIRECTION OUTPUT ;
    USE SIGNAL ;
    PORT
      LAYER M4 ;
        RECT  21.408 37.2 21.6 37.224 ;
    END
  END o2[52]
  PIN o2[53]
    DIRECTION OUTPUT ;
    USE SIGNAL ;
    PORT
      LAYER M4 ;
        RECT  21.408 37.392 21.6 37.416 ;
    END
  END o2[53]
  PIN o2[54]
    DIRECTION OUTPUT ;
    USE SIGNAL ;
    PORT
      LAYER M4 ;
        RECT  21.408 37.584 21.6 37.608 ;
    END
  END o2[54]
  PIN o2[55]
    DIRECTION OUTPUT ;
    USE SIGNAL ;
    PORT
      LAYER M4 ;
        RECT  21.408 37.728 21.6 37.752 ;
    END
  END o2[55]
  PIN o2[56]
    DIRECTION OUTPUT ;
    USE SIGNAL ;
    PORT
      LAYER M4 ;
        RECT  21.408 37.92 21.6 37.944 ;
    END
  END o2[56]
  PIN o2[57]
    DIRECTION OUTPUT ;
    USE SIGNAL ;
    PORT
      LAYER M4 ;
        RECT  21.408 38.064 21.6 38.088 ;
    END
  END o2[57]
  PIN o2[58]
    DIRECTION OUTPUT ;
    USE SIGNAL ;
    PORT
      LAYER M4 ;
        RECT  21.408 38.256 21.6 38.28 ;
    END
  END o2[58]
  PIN o2[59]
    DIRECTION OUTPUT ;
    USE SIGNAL ;
    PORT
      LAYER M4 ;
        RECT  21.408 38.448 21.6 38.472 ;
    END
  END o2[59]
  PIN o2[5]
    DIRECTION OUTPUT ;
    USE SIGNAL ;
    PORT
      LAYER M4 ;
        RECT  21.408 29.136 21.6 29.16 ;
    END
  END o2[5]
  PIN o2[60]
    DIRECTION OUTPUT ;
    USE SIGNAL ;
    PORT
      LAYER M4 ;
        RECT  21.408 38.592 21.6 38.616 ;
    END
  END o2[60]
  PIN o2[61]
    DIRECTION OUTPUT ;
    USE SIGNAL ;
    PORT
      LAYER M4 ;
        RECT  21.408 38.784 21.6 38.808 ;
    END
  END o2[61]
  PIN o2[62]
    DIRECTION OUTPUT ;
    USE SIGNAL ;
    PORT
      LAYER M4 ;
        RECT  21.408 38.928 21.6 38.952 ;
    END
  END o2[62]
  PIN o2[63]
    DIRECTION OUTPUT ;
    USE SIGNAL ;
    PORT
      LAYER M4 ;
        RECT  21.408 39.12 21.6 39.144 ;
    END
  END o2[63]
  PIN o2[64]
    DIRECTION OUTPUT ;
    USE SIGNAL ;
    PORT
      LAYER M4 ;
        RECT  21.408 39.264 21.6 39.288 ;
    END
  END o2[64]
  PIN o2[65]
    DIRECTION OUTPUT ;
    USE SIGNAL ;
    PORT
      LAYER M4 ;
        RECT  21.408 39.456 21.6 39.48 ;
    END
  END o2[65]
  PIN o2[66]
    DIRECTION OUTPUT ;
    USE SIGNAL ;
    PORT
      LAYER M4 ;
        RECT  21.408 39.648 21.6 39.672 ;
    END
  END o2[66]
  PIN o2[67]
    DIRECTION OUTPUT ;
    USE SIGNAL ;
    PORT
      LAYER M4 ;
        RECT  21.408 39.792 21.6 39.816 ;
    END
  END o2[67]
  PIN o2[68]
    DIRECTION OUTPUT ;
    USE SIGNAL ;
    PORT
      LAYER M4 ;
        RECT  21.408 40.128 21.6 40.152 ;
    END
  END o2[68]
  PIN o2[69]
    DIRECTION OUTPUT ;
    USE SIGNAL ;
    PORT
      LAYER M4 ;
        RECT  21.408 40.32 21.6 40.344 ;
    END
  END o2[69]
  PIN o2[6]
    DIRECTION OUTPUT ;
    USE SIGNAL ;
    PORT
      LAYER M4 ;
        RECT  21.408 29.328 21.6 29.352 ;
    END
  END o2[6]
  PIN o2[70]
    DIRECTION OUTPUT ;
    USE SIGNAL ;
    PORT
      LAYER M4 ;
        RECT  21.408 40.464 21.6 40.488 ;
    END
  END o2[70]
  PIN o2[71]
    DIRECTION OUTPUT ;
    USE SIGNAL ;
    PORT
      LAYER M4 ;
        RECT  21.408 40.656 21.6 40.68 ;
    END
  END o2[71]
  PIN o2[72]
    DIRECTION OUTPUT ;
    USE SIGNAL ;
    PORT
      LAYER M4 ;
        RECT  21.408 40.848 21.6 40.872 ;
    END
  END o2[72]
  PIN o2[73]
    DIRECTION OUTPUT ;
    USE SIGNAL ;
    PORT
      LAYER M4 ;
        RECT  21.408 40.992 21.6 41.016 ;
    END
  END o2[73]
  PIN o2[74]
    DIRECTION OUTPUT ;
    USE SIGNAL ;
    PORT
      LAYER M4 ;
        RECT  21.408 41.184 21.6 41.208 ;
    END
  END o2[74]
  PIN o2[75]
    DIRECTION OUTPUT ;
    USE SIGNAL ;
    PORT
      LAYER M4 ;
        RECT  21.408 41.328 21.6 41.352 ;
    END
  END o2[75]
  PIN o2[76]
    DIRECTION OUTPUT ;
    USE SIGNAL ;
    PORT
      LAYER M4 ;
        RECT  21.408 41.52 21.6 41.544 ;
    END
  END o2[76]
  PIN o2[77]
    DIRECTION OUTPUT ;
    USE SIGNAL ;
    PORT
      LAYER M4 ;
        RECT  21.408 41.712 21.6 41.736 ;
    END
  END o2[77]
  PIN o2[78]
    DIRECTION OUTPUT ;
    USE SIGNAL ;
    PORT
      LAYER M4 ;
        RECT  21.408 41.856 21.6 41.88 ;
    END
  END o2[78]
  PIN o2[79]
    DIRECTION OUTPUT ;
    USE SIGNAL ;
    PORT
      LAYER M4 ;
        RECT  21.408 42.048 21.6 42.072 ;
    END
  END o2[79]
  PIN o2[7]
    DIRECTION OUTPUT ;
    USE SIGNAL ;
    PORT
      LAYER M4 ;
        RECT  21.408 29.472 21.6 29.496 ;
    END
  END o2[7]
  PIN o2[80]
    DIRECTION OUTPUT ;
    USE SIGNAL ;
    PORT
      LAYER M4 ;
        RECT  21.408 42.192 21.6 42.216 ;
    END
  END o2[80]
  PIN o2[81]
    DIRECTION OUTPUT ;
    USE SIGNAL ;
    PORT
      LAYER M4 ;
        RECT  21.408 42.384 21.6 42.408 ;
    END
  END o2[81]
  PIN o2[82]
    DIRECTION OUTPUT ;
    USE SIGNAL ;
    PORT
      LAYER M4 ;
        RECT  21.408 42.528 21.6 42.552 ;
    END
  END o2[82]
  PIN o2[83]
    DIRECTION OUTPUT ;
    USE SIGNAL ;
    PORT
      LAYER M4 ;
        RECT  21.408 42.72 21.6 42.744 ;
    END
  END o2[83]
  PIN o2[84]
    DIRECTION OUTPUT ;
    USE SIGNAL ;
    PORT
      LAYER M4 ;
        RECT  21.408 42.912 21.6 42.936 ;
    END
  END o2[84]
  PIN o2[85]
    DIRECTION OUTPUT ;
    USE SIGNAL ;
    PORT
      LAYER M4 ;
        RECT  21.408 43.056 21.6 43.08 ;
    END
  END o2[85]
  PIN o2[86]
    DIRECTION OUTPUT ;
    USE SIGNAL ;
    PORT
      LAYER M4 ;
        RECT  21.408 43.248 21.6 43.272 ;
    END
  END o2[86]
  PIN o2[87]
    DIRECTION OUTPUT ;
    USE SIGNAL ;
    PORT
      LAYER M4 ;
        RECT  21.408 43.392 21.6 43.416 ;
    END
  END o2[87]
  PIN o2[88]
    DIRECTION OUTPUT ;
    USE SIGNAL ;
    PORT
      LAYER M4 ;
        RECT  21.408 43.584 21.6 43.608 ;
    END
  END o2[88]
  PIN o2[89]
    DIRECTION OUTPUT ;
    USE SIGNAL ;
    PORT
      LAYER M4 ;
        RECT  21.408 43.728 21.6 43.752 ;
    END
  END o2[89]
  PIN o2[8]
    DIRECTION OUTPUT ;
    USE SIGNAL ;
    PORT
      LAYER M4 ;
        RECT  21.408 29.664 21.6 29.688 ;
    END
  END o2[8]
  PIN o2[90]
    DIRECTION OUTPUT ;
    USE SIGNAL ;
    PORT
      LAYER M4 ;
        RECT  21.408 43.92 21.6 43.944 ;
    END
  END o2[90]
  PIN o2[91]
    DIRECTION OUTPUT ;
    USE SIGNAL ;
    PORT
      LAYER M4 ;
        RECT  21.408 44.112 21.6 44.136 ;
    END
  END o2[91]
  PIN o2[92]
    DIRECTION OUTPUT ;
    USE SIGNAL ;
    PORT
      LAYER M4 ;
        RECT  21.408 44.256 21.6 44.28 ;
    END
  END o2[92]
  PIN o2[93]
    DIRECTION OUTPUT ;
    USE SIGNAL ;
    PORT
      LAYER M4 ;
        RECT  21.408 44.448 21.6 44.472 ;
    END
  END o2[93]
  PIN o2[94]
    DIRECTION OUTPUT ;
    USE SIGNAL ;
    PORT
      LAYER M4 ;
        RECT  21.408 44.592 21.6 44.616 ;
    END
  END o2[94]
  PIN o2[95]
    DIRECTION OUTPUT ;
    USE SIGNAL ;
    PORT
      LAYER M4 ;
        RECT  21.408 44.784 21.6 44.808 ;
    END
  END o2[95]
  PIN o2[96]
    DIRECTION OUTPUT ;
    USE SIGNAL ;
    PORT
      LAYER M4 ;
        RECT  21.408 44.976 21.6 45 ;
    END
  END o2[96]
  PIN o2[97]
    DIRECTION OUTPUT ;
    USE SIGNAL ;
    PORT
      LAYER M4 ;
        RECT  21.408 45.12 21.6 45.144 ;
    END
  END o2[97]
  PIN o2[98]
    DIRECTION OUTPUT ;
    USE SIGNAL ;
    PORT
      LAYER M4 ;
        RECT  21.408 45.312 21.6 45.336 ;
    END
  END o2[98]
  PIN o2[99]
    DIRECTION OUTPUT ;
    USE SIGNAL ;
    PORT
      LAYER M4 ;
        RECT  21.408 45.456 21.6 45.48 ;
    END
  END o2[99]
  PIN o2[9]
    DIRECTION OUTPUT ;
    USE SIGNAL ;
    PORT
      LAYER M4 ;
        RECT  21.408 29.856 21.6 29.88 ;
    END
  END o2[9]
  PIN rs
    DIRECTION INPUT ;
    USE SIGNAL ;
    PORT
      LAYER M5 ;
        RECT  10.8 0 10.824 0.192 ;
    END
  END rs
  PIN VDD
    DIRECTION INOUT ;
    USE POWER ;
    PORT
      LAYER M5 ;
        RECT  18.792 2.151 18.912 54.009 ;
        RECT  16.092 2.151 16.212 54.009 ;
        RECT  13.392 2.151 13.512 54.009 ;
        RECT  10.692 2.151 10.812 54.009 ;
        RECT  7.992 2.151 8.112 54.009 ;
        RECT  5.292 2.151 5.412 54.009 ;
        RECT  2.592 2.151 2.712 54.009 ;
    END
  END VDD
  PIN VSS
    DIRECTION INOUT ;
    USE GROUND ;
    PORT
      LAYER M5 ;
        RECT  18.6 2.137 18.72 54.023 ;
        RECT  15.9 2.137 16.02 54.023 ;
        RECT  13.2 2.137 13.32 54.023 ;
        RECT  10.5 2.137 10.62 54.023 ;
        RECT  7.8 2.137 7.92 54.023 ;
        RECT  5.1 2.137 5.22 54.023 ;
        RECT  2.4 2.137 2.52 54.023 ;
    END
  END VSS
  OBS
    LAYER RVTN ;
     RECT  2.16 2.16 19.44 2.295 ;
     RECT  2.16 2.565 19.44 2.835 ;
     RECT  2.16 3.105 19.44 3.375 ;
     RECT  2.16 3.645 19.44 3.915 ;
     RECT  2.16 4.185 19.44 4.455 ;
     RECT  2.16 4.725 19.44 4.995 ;
     RECT  2.16 5.265 19.44 5.535 ;
     RECT  2.16 5.805 19.44 6.075 ;
     RECT  2.16 6.345 19.44 6.615 ;
     RECT  2.16 6.885 19.44 7.155 ;
     RECT  2.16 7.425 19.44 7.695 ;
     RECT  2.16 7.965 19.44 8.235 ;
     RECT  2.16 8.505 19.44 8.775 ;
     RECT  2.16 9.045 19.44 9.315 ;
     RECT  2.16 9.585 19.44 9.855 ;
     RECT  2.16 10.125 19.44 10.395 ;
     RECT  2.16 10.665 19.44 10.935 ;
     RECT  2.16 11.205 19.44 11.475 ;
     RECT  2.16 11.745 19.44 12.015 ;
     RECT  2.16 12.285 19.44 12.555 ;
     RECT  2.16 12.825 19.44 13.095 ;
     RECT  2.16 13.365 19.44 13.635 ;
     RECT  2.16 13.905 19.44 14.175 ;
     RECT  2.16 14.445 19.44 14.715 ;
     RECT  2.16 14.985 19.44 15.255 ;
     RECT  2.16 15.525 19.44 15.795 ;
     RECT  2.16 16.065 19.44 16.335 ;
     RECT  2.16 16.605 19.44 16.875 ;
     RECT  2.16 17.145 19.44 17.415 ;
     RECT  2.16 17.685 19.44 17.955 ;
     RECT  2.16 18.225 19.44 18.495 ;
     RECT  2.16 18.765 19.44 19.035 ;
     RECT  2.16 19.305 19.44 19.575 ;
     RECT  2.16 19.845 19.44 20.115 ;
     RECT  2.16 20.385 19.44 20.655 ;
     RECT  2.16 20.925 19.44 21.195 ;
     RECT  2.16 21.465 19.44 21.735 ;
     RECT  2.16 22.005 19.44 22.275 ;
     RECT  2.16 22.545 19.44 22.815 ;
     RECT  2.16 23.085 19.44 23.355 ;
     RECT  2.16 23.625 19.44 23.895 ;
     RECT  2.16 24.165 19.44 24.435 ;
     RECT  2.16 24.705 19.44 24.975 ;
     RECT  2.16 25.245 19.44 25.515 ;
     RECT  2.16 25.785 19.44 26.055 ;
     RECT  2.16 26.325 19.44 26.595 ;
     RECT  2.16 26.865 19.44 27.135 ;
     RECT  2.16 27.405 19.44 27.675 ;
     RECT  2.16 27.945 19.44 28.215 ;
     RECT  2.16 28.485 19.44 28.755 ;
     RECT  2.16 29.025 19.44 29.295 ;
     RECT  2.16 29.565 19.44 29.835 ;
     RECT  2.16 30.105 19.44 30.375 ;
     RECT  2.16 30.645 19.44 30.915 ;
     RECT  2.16 31.185 19.44 31.455 ;
     RECT  2.16 31.725 19.44 31.995 ;
     RECT  2.16 32.265 19.44 32.535 ;
     RECT  2.16 32.805 19.44 33.075 ;
     RECT  2.16 33.345 19.44 33.615 ;
     RECT  2.16 33.885 19.44 34.155 ;
     RECT  2.16 34.425 19.44 34.695 ;
     RECT  2.16 34.965 19.44 35.235 ;
     RECT  2.16 35.505 19.44 35.775 ;
     RECT  2.16 36.045 19.44 36.315 ;
     RECT  2.16 36.585 19.44 36.855 ;
     RECT  2.16 37.125 19.44 37.395 ;
     RECT  2.16 37.665 19.44 37.935 ;
     RECT  2.16 38.205 19.44 38.475 ;
     RECT  2.16 38.745 19.44 39.015 ;
     RECT  2.16 39.285 19.44 39.555 ;
     RECT  2.16 39.825 19.44 40.095 ;
     RECT  2.16 40.365 19.44 40.635 ;
     RECT  2.16 40.905 19.44 41.175 ;
     RECT  2.16 41.445 19.44 41.715 ;
     RECT  2.16 41.985 19.44 42.255 ;
     RECT  2.16 42.525 19.44 42.795 ;
     RECT  2.16 43.065 19.44 43.335 ;
     RECT  2.16 43.605 19.44 43.875 ;
     RECT  2.16 44.145 19.44 44.415 ;
     RECT  2.16 44.685 19.44 44.955 ;
     RECT  2.16 45.225 19.44 45.495 ;
     RECT  2.16 45.765 19.44 46.035 ;
     RECT  2.16 46.305 19.44 46.575 ;
     RECT  2.16 46.845 19.44 47.115 ;
     RECT  2.16 47.385 19.44 47.655 ;
     RECT  2.16 47.925 19.44 48.195 ;
     RECT  2.16 48.465 19.44 48.735 ;
     RECT  2.16 49.005 19.44 49.275 ;
     RECT  2.16 49.545 19.44 49.815 ;
     RECT  2.16 50.085 19.44 50.355 ;
     RECT  2.16 50.625 19.44 50.895 ;
     RECT  2.16 51.165 19.44 51.435 ;
     RECT  2.16 51.705 19.44 51.975 ;
     RECT  2.16 52.245 19.44 52.515 ;
     RECT  2.16 52.785 19.44 53.055 ;
     RECT  2.16 53.325 19.44 53.595 ;
     RECT  2.16 53.865 19.44 54 ;
    LAYER RVTP ;
     RECT  2.16 2.295 19.44 2.565 ;
     RECT  2.16 2.835 19.44 3.105 ;
     RECT  2.16 3.375 19.44 3.645 ;
     RECT  2.16 3.915 19.44 4.185 ;
     RECT  2.16 4.455 19.44 4.725 ;
     RECT  2.16 4.995 19.44 5.265 ;
     RECT  2.16 5.535 19.44 5.805 ;
     RECT  2.16 6.075 19.44 6.345 ;
     RECT  2.16 6.615 19.44 6.885 ;
     RECT  2.16 7.155 19.44 7.425 ;
     RECT  2.16 7.695 19.44 7.965 ;
     RECT  2.16 8.235 19.44 8.505 ;
     RECT  2.16 8.775 19.44 9.045 ;
     RECT  2.16 9.315 19.44 9.585 ;
     RECT  2.16 9.855 19.44 10.125 ;
     RECT  2.16 10.395 19.44 10.665 ;
     RECT  2.16 10.935 19.44 11.205 ;
     RECT  2.16 11.475 19.44 11.745 ;
     RECT  2.16 12.015 19.44 12.285 ;
     RECT  2.16 12.555 19.44 12.825 ;
     RECT  2.16 13.095 19.44 13.365 ;
     RECT  2.16 13.635 19.44 13.905 ;
     RECT  2.16 14.175 19.44 14.445 ;
     RECT  2.16 14.715 19.44 14.985 ;
     RECT  2.16 15.255 19.44 15.525 ;
     RECT  2.16 15.795 19.44 16.065 ;
     RECT  2.16 16.335 19.44 16.605 ;
     RECT  2.16 16.875 19.44 17.145 ;
     RECT  2.16 17.415 19.44 17.685 ;
     RECT  2.16 17.955 19.44 18.225 ;
     RECT  2.16 18.495 19.44 18.765 ;
     RECT  2.16 19.035 19.44 19.305 ;
     RECT  2.16 19.575 19.44 19.845 ;
     RECT  2.16 20.115 19.44 20.385 ;
     RECT  2.16 20.655 19.44 20.925 ;
     RECT  2.16 21.195 19.44 21.465 ;
     RECT  2.16 21.735 19.44 22.005 ;
     RECT  2.16 22.275 19.44 22.545 ;
     RECT  2.16 22.815 19.44 23.085 ;
     RECT  2.16 23.355 19.44 23.625 ;
     RECT  2.16 23.895 19.44 24.165 ;
     RECT  2.16 24.435 19.44 24.705 ;
     RECT  2.16 24.975 19.44 25.245 ;
     RECT  2.16 25.515 19.44 25.785 ;
     RECT  2.16 26.055 19.44 26.325 ;
     RECT  2.16 26.595 19.44 26.865 ;
     RECT  2.16 27.135 19.44 27.405 ;
     RECT  2.16 27.675 19.44 27.945 ;
     RECT  2.16 28.215 19.44 28.485 ;
     RECT  2.16 28.755 19.44 29.025 ;
     RECT  2.16 29.295 19.44 29.565 ;
     RECT  2.16 29.835 19.44 30.105 ;
     RECT  2.16 30.375 19.44 30.645 ;
     RECT  2.16 30.915 19.44 31.185 ;
     RECT  2.16 31.455 19.44 31.725 ;
     RECT  2.16 31.995 19.44 32.265 ;
     RECT  2.16 32.535 19.44 32.805 ;
     RECT  2.16 33.075 19.44 33.345 ;
     RECT  2.16 33.615 19.44 33.885 ;
     RECT  2.16 34.155 19.44 34.425 ;
     RECT  2.16 34.695 19.44 34.965 ;
     RECT  2.16 35.235 19.44 35.505 ;
     RECT  2.16 35.775 19.44 36.045 ;
     RECT  2.16 36.315 19.44 36.585 ;
     RECT  2.16 36.855 19.44 37.125 ;
     RECT  2.16 37.395 19.44 37.665 ;
     RECT  2.16 37.935 19.44 38.205 ;
     RECT  2.16 38.475 19.44 38.745 ;
     RECT  2.16 39.015 19.44 39.285 ;
     RECT  2.16 39.555 19.44 39.825 ;
     RECT  2.16 40.095 19.44 40.365 ;
     RECT  2.16 40.635 19.44 40.905 ;
     RECT  2.16 41.175 19.44 41.445 ;
     RECT  2.16 41.715 19.44 41.985 ;
     RECT  2.16 42.255 19.44 42.525 ;
     RECT  2.16 42.795 19.44 43.065 ;
     RECT  2.16 43.335 19.44 43.605 ;
     RECT  2.16 43.875 19.44 44.145 ;
     RECT  2.16 44.415 19.44 44.685 ;
     RECT  2.16 44.955 19.44 45.225 ;
     RECT  2.16 45.495 19.44 45.765 ;
     RECT  2.16 46.035 19.44 46.305 ;
     RECT  2.16 46.575 19.44 46.845 ;
     RECT  2.16 47.115 19.44 47.385 ;
     RECT  2.16 47.655 19.44 47.925 ;
     RECT  2.16 48.195 19.44 48.465 ;
     RECT  2.16 48.735 19.44 49.005 ;
     RECT  2.16 49.275 19.44 49.545 ;
     RECT  2.16 49.815 19.44 50.085 ;
     RECT  2.16 50.355 19.44 50.625 ;
     RECT  2.16 50.895 19.44 51.165 ;
     RECT  2.16 51.435 19.44 51.705 ;
     RECT  2.16 51.975 19.44 52.245 ;
     RECT  2.16 52.515 19.44 52.785 ;
     RECT  2.16 53.055 19.44 53.325 ;
     RECT  2.16 53.595 19.44 53.865 ;
    LAYER M1 ;
     RECT  2.16 2.151 19.44 54.009 ;
    LAYER M2 ;
     RECT  0.211 15.336 0.311 15.354 ;
     RECT  0.211 26.676 0.311 26.694 ;
     RECT  0.211 49.896 0.311 50.454 ;
     RECT  0.247 32.976 0.499 32.994 ;
     RECT  0.211 35.406 0.499 35.424 ;
     RECT  0.211 37.026 0.499 37.044 ;
     RECT  0.211 44.496 0.499 45.144 ;
     RECT  0.211 21.006 0.535 21.024 ;
     RECT  0.499 31.734 0.535 31.752 ;
     RECT  0.499 32.616 0.535 32.994 ;
     RECT  0.499 35.244 0.535 35.424 ;
     RECT  0.499 37.026 0.535 37.116 ;
     RECT  0.499 44.154 0.535 45.144 ;
     RECT  0.211 48.906 0.535 48.924 ;
     RECT  0.319 5.166 2.16 5.184 ;
     RECT  0.535 6.246 2.16 6.264 ;
     RECT  0.535 7.866 2.16 7.884 ;
     RECT  0.247 11.718 2.16 11.736 ;
     RECT  0.211 14.256 2.16 14.274 ;
     RECT  0.211 16.686 2.16 16.902 ;
     RECT  0.535 21.006 2.16 21.654 ;
     RECT  0.535 23.256 2.16 23.814 ;
     RECT  0.535 27.144 2.16 27.162 ;
     RECT  0.535 29.538 2.16 29.556 ;
     RECT  0.535 30.654 2.16 30.672 ;
     RECT  0.535 31.734 2.16 33.606 ;
     RECT  0.535 34.74 2.16 37.116 ;
     RECT  0.535 38.178 2.16 39.312 ;
     RECT  0.535 41.346 2.16 41.364 ;
     RECT  0.535 42.336 2.16 42.354 ;
     RECT  0.535 43.776 2.16 45.144 ;
     RECT  0.535 47.286 2.16 47.304 ;
     RECT  0.535 48.366 2.16 48.924 ;
     RECT  0.311 49.896 2.16 49.914 ;
     RECT  2.16 2.151 19.44 54.009 ;
     RECT  19.44 5.85 19.571 11.538 ;
     RECT  19.44 12.294 19.643 19.566 ;
     RECT  19.643 12.528 19.715 19.566 ;
     RECT  19.44 4.23 19.967 4.248 ;
     RECT  19.571 5.85 19.967 9.108 ;
     RECT  19.571 10.098 19.967 11.538 ;
     RECT  19.715 12.528 19.967 12.816 ;
     RECT  19.715 13.608 19.967 19.566 ;
     RECT  19.44 40.104 19.967 51.534 ;
     RECT  19.967 5.85 20.003 5.868 ;
     RECT  19.967 8.82 20.003 9.036 ;
     RECT  19.967 14.256 20.003 14.436 ;
     RECT  19.967 15.768 20.003 15.786 ;
     RECT  19.967 16.956 20.003 18.216 ;
     RECT  19.44 20.43 20.003 21.996 ;
     RECT  19.44 25.218 20.003 39.312 ;
     RECT  19.967 40.104 20.003 40.392 ;
     RECT  19.967 41.148 20.003 46.764 ;
     RECT  20.003 8.82 20.039 8.838 ;
     RECT  20.003 36.522 20.039 38.934 ;
     RECT  19.967 11.178 20.075 11.538 ;
     RECT  20.003 21.168 20.075 21.996 ;
     RECT  20.003 41.994 20.075 43.632 ;
     RECT  20.075 11.484 20.507 11.538 ;
     RECT  20.039 36.522 20.507 38.664 ;
     RECT  20.003 45.306 20.507 46.53 ;
     RECT  19.967 7.398 20.543 7.416 ;
     RECT  20.507 11.484 20.543 11.502 ;
     RECT  20.003 14.256 20.543 14.274 ;
     RECT  20.003 16.956 20.543 16.974 ;
     RECT  20.075 21.438 20.543 21.996 ;
     RECT  19.44 22.788 20.543 24.426 ;
     RECT  20.003 25.218 20.543 35.46 ;
     RECT  20.507 36.828 20.543 38.664 ;
     RECT  20.003 40.374 20.543 40.392 ;
     RECT  20.003 41.148 20.543 41.166 ;
     RECT  20.075 41.994 20.543 43.326 ;
     RECT  20.003 44.424 20.543 44.442 ;
     RECT  20.507 45.306 20.543 46.098 ;
     RECT  19.967 47.664 20.543 49.572 ;
     RECT  19.967 50.796 20.543 51.534 ;
     RECT  20.543 24.408 20.579 24.426 ;
     RECT  20.543 27.342 20.579 29.484 ;
     RECT  20.543 32.202 20.579 32.22 ;
     RECT  20.543 33.93 20.579 33.948 ;
     RECT  20.543 35.442 20.579 35.46 ;
     RECT  20.543 36.828 20.579 36.846 ;
     RECT  20.543 42.696 20.579 43.326 ;
     RECT  20.543 46.008 20.579 46.026 ;
     RECT  20.543 48.636 20.579 49.5 ;
     RECT  20.543 38.178 20.615 38.196 ;
     RECT  20.579 49.482 20.615 49.5 ;
     RECT  20.543 31.086 21.407 31.104 ;
     RECT  21.379 9.522 21.479 9.54 ;
     RECT  21.379 11.952 21.479 11.97 ;
     RECT  21.379 29.106 21.479 29.124 ;
    LAYER M3 ;
     RECT  10.8 1.723 10.818 2.143 ;
     RECT  10.515 2.143 10.818 2.371 ;
     RECT  2.415 2.143 2.505 2.413 ;
     RECT  5.115 2.143 5.205 2.413 ;
     RECT  7.815 2.143 7.905 2.413 ;
     RECT  13.215 2.143 13.305 2.413 ;
     RECT  15.915 2.143 16.005 2.413 ;
     RECT  18.615 2.143 18.705 2.413 ;
     RECT  10.515 2.371 10.854 2.641 ;
     RECT  18.615 2.413 18.897 3.685 ;
     RECT  18.615 3.685 19.098 3.721 ;
     RECT  15.915 2.413 16.197 3.991 ;
     RECT  18.615 3.721 19.242 3.991 ;
     RECT  15.915 3.991 16.686 4.117 ;
     RECT  18.252 3.991 19.242 4.117 ;
     RECT  10.515 2.641 10.962 4.145 ;
     RECT  15.915 4.117 16.902 4.153 ;
     RECT  17.712 4.117 19.242 4.153 ;
     RECT  15.915 4.153 19.242 4.225 ;
     RECT  2.415 2.413 2.697 4.495 ;
     RECT  15.915 4.225 19.962 4.495 ;
     RECT  15.3 4.495 19.962 4.541 ;
     RECT  2.415 4.495 2.934 4.621 ;
     RECT  15.3 4.541 19.278 4.621 ;
     RECT  13.215 2.413 13.497 4.693 ;
     RECT  2.304 4.621 2.934 4.765 ;
     RECT  5.115 2.413 5.397 4.765 ;
     RECT  12.78 4.693 13.497 4.765 ;
     RECT  15.156 4.621 19.278 4.765 ;
     RECT  2.304 4.765 3.474 4.801 ;
     RECT  11.916 4.261 11.934 4.801 ;
     RECT  12.672 4.765 13.497 4.801 ;
     RECT  4.428 4.765 5.397 4.928 ;
     RECT  14.832 4.765 19.278 4.955 ;
     RECT  10.515 4.145 10.89 4.991 ;
     RECT  0.252 4.891 0.27 5.021 ;
     RECT  2.304 4.801 3.546 5.063 ;
     RECT  14.832 4.955 19.206 5.071 ;
     RECT  6.12 4.891 6.138 5.161 ;
     RECT  0.324 5.035 0.342 5.189 ;
     RECT  5.115 4.928 5.397 5.197 ;
     RECT  6.12 5.161 6.642 5.197 ;
     RECT  11.916 4.801 13.497 5.233 ;
     RECT  14.256 5.071 19.206 5.233 ;
     RECT  8.856 5.305 8.874 5.341 ;
     RECT  5.115 5.197 6.642 5.369 ;
     RECT  6.588 5.369 6.642 5.431 ;
     RECT  8.856 5.341 8.946 5.531 ;
     RECT  6.588 5.431 6.858 5.575 ;
     RECT  6.588 5.575 6.966 5.605 ;
     RECT  7.815 2.413 8.097 5.605 ;
     RECT  11.916 5.233 19.206 5.605 ;
     RECT  6.588 5.605 8.097 5.645 ;
     RECT  6.948 5.645 6.966 5.729 ;
     RECT  2.304 5.063 2.97 5.845 ;
     RECT  3.996 5.227 4.014 5.845 ;
     RECT  5.115 5.369 5.742 5.845 ;
     RECT  19.944 5.707 19.962 5.845 ;
     RECT  2.304 5.845 5.742 5.933 ;
     RECT  19.944 5.845 19.998 5.933 ;
     RECT  11.88 5.605 19.206 5.971 ;
     RECT  19.944 5.933 19.962 5.971 ;
     RECT  2.415 5.933 5.742 6.143 ;
     RECT  3.996 6.143 5.742 6.341 ;
     RECT  4.968 6.341 5.742 6.449 ;
     RECT  0.54 6.241 0.558 6.461 ;
     RECT  11.88 5.971 19.962 6.539 ;
     RECT  3.996 6.341 4.158 6.605 ;
     RECT  11.88 6.539 19.098 6.619 ;
     RECT  3.996 6.605 4.05 6.809 ;
     RECT  0.216 6.667 0.234 6.989 ;
     RECT  4.968 6.449 5.397 6.989 ;
     RECT  2.415 6.143 2.862 7.087 ;
     RECT  3.996 6.809 4.014 7.087 ;
     RECT  10.515 4.991 10.797 7.123 ;
     RECT  8.856 5.531 8.874 7.195 ;
     RECT  6.12 6.511 6.354 7.231 ;
     RECT  10.515 7.123 10.926 7.259 ;
     RECT  6.12 7.231 6.606 7.321 ;
     RECT  5.004 6.989 5.397 7.349 ;
     RECT  5.076 7.349 5.397 7.357 ;
     RECT  6.12 7.321 7.038 7.357 ;
     RECT  7.815 5.645 8.097 7.357 ;
     RECT  19.944 6.539 19.962 7.393 ;
     RECT  19.944 7.393 20.538 7.469 ;
     RECT  11.664 6.619 19.098 7.501 ;
     RECT  19.944 7.469 19.962 7.501 ;
     RECT  5.076 7.357 8.097 7.529 ;
     RECT  5.115 7.529 8.097 7.619 ;
     RECT  11.664 7.501 19.962 7.619 ;
     RECT  2.415 7.087 4.014 7.699 ;
     RECT  0.252 7.675 0.27 7.805 ;
     RECT  2.415 7.699 4.122 7.861 ;
     RECT  11.664 7.619 19.17 7.889 ;
     RECT  2.415 7.861 4.266 8.069 ;
     RECT  5.115 7.619 6.714 8.069 ;
     RECT  0.54 7.861 0.558 8.189 ;
     RECT  8.856 7.195 9.414 8.239 ;
     RECT  6.264 8.069 6.714 8.339 ;
     RECT  8.856 8.239 9.702 8.401 ;
     RECT  10.515 7.259 10.854 8.401 ;
     RECT  3.744 8.069 4.266 8.545 ;
     RECT  8.856 8.401 10.854 8.545 ;
     RECT  3.744 8.545 4.338 8.581 ;
     RECT  5.115 8.069 5.397 8.581 ;
     RECT  6.516 8.339 6.714 8.779 ;
     RECT  8.856 8.545 10.926 8.807 ;
     RECT  0.252 8.635 0.27 8.813 ;
     RECT  2.415 8.069 3.006 8.815 ;
     RECT  3.744 8.581 5.397 8.815 ;
     RECT  19.944 7.619 19.962 8.815 ;
     RECT  2.415 8.815 5.397 8.827 ;
     RECT  2.304 8.827 5.397 8.879 ;
     RECT  2.304 8.879 3.51 8.969 ;
     RECT  6.516 8.779 7.002 8.969 ;
     RECT  11.664 7.889 19.134 8.977 ;
     RECT  19.944 8.815 20.034 9.005 ;
     RECT  19.944 9.005 19.998 9.041 ;
     RECT  11.664 8.977 19.17 9.121 ;
     RECT  19.944 9.041 19.962 9.121 ;
     RECT  4.248 8.879 5.397 9.239 ;
     RECT  0.216 9.163 0.234 9.293 ;
     RECT  6.516 8.969 6.534 9.355 ;
     RECT  21.384 9.499 21.402 9.517 ;
     RECT  4.248 9.239 4.266 9.533 ;
     RECT  21.384 9.517 21.474 9.545 ;
     RECT  21.456 9.545 21.474 9.581 ;
     RECT  2.304 8.969 2.898 9.751 ;
     RECT  8.856 8.807 10.797 9.823 ;
     RECT  2.304 9.751 3.186 9.859 ;
     RECT  3.996 9.787 4.014 9.859 ;
     RECT  5.004 9.239 5.397 9.859 ;
     RECT  6.336 9.355 6.534 9.859 ;
     RECT  11.664 9.121 19.962 10.229 ;
     RECT  2.304 9.859 4.014 10.319 ;
     RECT  5.004 9.859 6.822 10.499 ;
     RECT  2.34 10.319 4.014 10.669 ;
     RECT  12.564 10.229 19.962 10.699 ;
     RECT  2.34 10.669 4.086 10.705 ;
     RECT  5.004 10.499 6.606 10.705 ;
     RECT  2.34 10.705 6.606 10.769 ;
     RECT  2.415 10.769 6.606 10.859 ;
     RECT  11.664 10.229 11.682 10.975 ;
     RECT  12.564 10.699 20.07 10.975 ;
     RECT  8.856 9.823 10.854 11.011 ;
     RECT  11.664 10.975 20.07 11.011 ;
     RECT  0.216 11.035 0.234 11.165 ;
     RECT  8.856 11.011 20.07 11.201 ;
     RECT  7.815 7.619 8.097 11.209 ;
     RECT  8.856 11.201 19.602 11.209 ;
     RECT  3.996 10.859 6.606 11.399 ;
     RECT  7.815 11.209 19.602 11.399 ;
     RECT  4.248 11.399 6.606 11.443 ;
     RECT  20.484 11.227 20.538 11.507 ;
     RECT  20.484 11.507 20.502 11.543 ;
     RECT  7.815 11.399 8.097 11.551 ;
     RECT  2.415 10.859 2.862 11.563 ;
     RECT  4.248 11.443 7.002 11.579 ;
     RECT  2.304 11.563 2.862 11.641 ;
     RECT  2.304 11.641 2.934 11.669 ;
     RECT  7.74 11.551 8.097 11.669 ;
     RECT  2.415 11.669 2.934 11.713 ;
     RECT  2.415 11.713 3.078 11.749 ;
     RECT  4.248 11.579 6.93 11.849 ;
     RECT  0.252 11.713 0.27 11.933 ;
     RECT  4.392 11.849 6.93 11.939 ;
     RECT  21.384 11.899 21.402 11.947 ;
     RECT  21.384 11.947 21.474 11.975 ;
     RECT  21.456 11.975 21.474 11.984 ;
     RECT  8.856 11.399 19.602 12.289 ;
     RECT  2.415 11.749 3.15 12.427 ;
     RECT  8.856 12.289 19.638 12.427 ;
     RECT  2.196 12.427 3.15 12.551 ;
     RECT  2.304 12.551 3.15 12.595 ;
     RECT  2.304 12.595 3.438 12.829 ;
     RECT  4.536 11.939 6.858 12.829 ;
     RECT  2.304 12.829 3.726 12.989 ;
     RECT  2.415 12.989 3.726 13.019 ;
     RECT  3.636 13.019 3.726 13.099 ;
     RECT  4.536 12.829 6.894 13.099 ;
     RECT  3.636 13.099 6.894 13.289 ;
     RECT  2.415 13.019 2.898 13.325 ;
     RECT  3.672 13.289 6.894 13.405 ;
     RECT  7.815 11.669 8.097 13.405 ;
     RECT  8.856 12.427 19.962 13.627 ;
     RECT  0.252 13.339 0.27 13.997 ;
     RECT  8.856 13.627 19.998 14.251 ;
     RECT  2.415 13.325 2.862 14.485 ;
     RECT  8.856 14.251 20.538 14.717 ;
     RECT  2.415 14.485 2.898 15.151 ;
     RECT  3.672 13.405 8.097 15.151 ;
     RECT  0.216 14.155 0.234 15.307 ;
     RECT  0.216 15.307 0.306 15.359 ;
     RECT  2.415 15.151 8.097 15.493 ;
     RECT  8.856 14.717 19.998 15.493 ;
     RECT  2.415 15.493 19.998 15.691 ;
     RECT  2.304 15.691 19.998 15.719 ;
     RECT  8.856 15.719 19.998 15.791 ;
     RECT  0.216 15.359 0.234 15.917 ;
     RECT  2.304 15.719 8.097 16.259 ;
     RECT  2.415 16.259 8.097 16.529 ;
     RECT  8.856 15.791 19.962 16.951 ;
     RECT  0.216 16.681 0.234 17.117 ;
     RECT  8.856 16.951 20.538 17.117 ;
     RECT  2.415 16.529 2.862 17.227 ;
     RECT  2.304 17.227 2.862 17.725 ;
     RECT  3.672 16.529 8.097 17.725 ;
     RECT  0.288 17.467 0.306 18.125 ;
     RECT  8.856 17.117 19.998 18.221 ;
     RECT  2.304 17.725 8.097 18.833 ;
     RECT  6.12 18.833 7.074 20.107 ;
     RECT  7.815 18.833 8.097 20.107 ;
     RECT  2.304 18.833 5.397 20.111 ;
     RECT  0.252 19.963 0.27 20.141 ;
     RECT  3.672 20.111 5.397 20.155 ;
     RECT  6.12 20.107 8.097 20.155 ;
     RECT  8.856 18.221 19.962 20.425 ;
     RECT  8.856 20.425 19.998 21.163 ;
     RECT  8.856 21.163 20.07 21.355 ;
     RECT  2.304 20.111 2.862 21.397 ;
     RECT  0.216 21.001 0.234 21.485 ;
     RECT  2.304 21.397 2.934 21.677 ;
     RECT  0.54 21.631 0.558 21.917 ;
     RECT  8.856 21.355 20.538 22.001 ;
     RECT  2.415 21.677 2.934 22.009 ;
     RECT  3.672 20.155 8.097 22.009 ;
     RECT  0.288 22.411 0.306 22.541 ;
     RECT  8.856 22.001 20.07 22.549 ;
     RECT  2.415 22.009 8.097 22.555 ;
     RECT  2.304 22.555 8.097 22.739 ;
     RECT  8.82 22.549 20.07 22.783 ;
     RECT  2.415 22.739 8.097 22.919 ;
     RECT  0.54 23.251 0.558 23.659 ;
     RECT  0.252 23.659 0.558 23.981 ;
     RECT  8.82 22.783 20.538 24.091 ;
     RECT  2.415 22.919 4.338 24.097 ;
     RECT  2.376 24.097 4.338 24.133 ;
     RECT  5.115 22.919 8.097 24.133 ;
     RECT  2.376 24.133 8.097 24.359 ;
     RECT  0.216 24.283 0.234 24.413 ;
     RECT  8.82 24.091 20.574 24.431 ;
     RECT  2.376 24.359 2.934 24.811 ;
     RECT  2.304 24.811 2.934 25.447 ;
     RECT  3.672 24.359 8.097 25.447 ;
     RECT  2.304 25.447 8.097 25.619 ;
     RECT  2.415 25.619 8.097 26.249 ;
     RECT  2.415 26.249 2.898 26.347 ;
     RECT  0.216 26.491 0.234 26.635 ;
     RECT  0.216 26.635 0.306 26.717 ;
     RECT  2.304 26.347 2.898 26.789 ;
     RECT  8.82 24.431 20.538 27.202 ;
     RECT  0.54 27.139 0.558 27.389 ;
     RECT  2.304 26.789 2.862 27.679 ;
     RECT  3.672 26.249 8.097 27.679 ;
     RECT  2.304 27.679 8.097 27.905 ;
     RECT  8.82 27.202 20.574 28.175 ;
     RECT  0.252 28.651 0.27 28.781 ;
     RECT  2.412 27.905 8.097 29.101 ;
     RECT  21.456 29.083 21.474 29.101 ;
     RECT  21.384 29.101 21.474 29.129 ;
     RECT  21.384 29.129 21.402 29.165 ;
     RECT  14.796 28.175 20.574 29.191 ;
     RECT  8.82 28.175 13.806 29.263 ;
     RECT  8.82 29.263 13.842 29.399 ;
     RECT  0.54 29.533 0.558 29.693 ;
     RECT  14.652 29.191 20.574 29.693 ;
     RECT  2.304 29.101 8.097 30.371 ;
     RECT  2.304 30.371 2.826 30.605 ;
     RECT  0.54 30.649 0.558 30.893 ;
     RECT  8.82 29.399 13.806 30.991 ;
     RECT  14.652 29.693 20.538 30.991 ;
     RECT  0.216 30.955 0.234 31.085 ;
     RECT  8.82 30.991 20.538 31.109 ;
     RECT  21.384 31.051 21.402 31.109 ;
     RECT  3.636 30.371 8.097 31.261 ;
     RECT  2.304 30.605 2.697 31.351 ;
     RECT  3.6 31.261 8.097 31.351 ;
     RECT  14.832 31.109 20.538 31.379 ;
     RECT  0.504 31.729 0.522 31.891 ;
     RECT  2.304 31.351 8.097 31.955 ;
     RECT  8.82 31.109 13.806 32.161 ;
     RECT  14.904 31.379 20.538 32.161 ;
     RECT  8.82 32.161 20.538 32.197 ;
     RECT  8.82 32.197 20.574 32.261 ;
     RECT  0.504 31.891 0.558 32.299 ;
     RECT  8.82 32.261 13.77 32.495 ;
     RECT  0.252 32.299 0.558 32.621 ;
     RECT  14.544 32.261 20.574 32.765 ;
     RECT  14.544 32.765 20.538 32.801 ;
     RECT  0.252 32.621 0.522 32.923 ;
     RECT  0.216 32.923 0.522 33.053 ;
     RECT  0.252 33.053 0.522 33.485 ;
     RECT  8.82 32.495 13.698 33.547 ;
     RECT  14.832 32.801 20.538 33.547 ;
     RECT  2.415 31.955 8.097 33.817 ;
     RECT  0.54 33.583 0.558 33.821 ;
     RECT  2.376 33.817 8.097 33.889 ;
     RECT  8.82 33.547 20.538 33.925 ;
     RECT  8.82 33.925 20.574 33.953 ;
     RECT  2.304 33.889 8.097 34.013 ;
     RECT  8.82 33.953 13.698 34.079 ;
     RECT  14.652 33.953 20.574 34.151 ;
     RECT  14.832 34.151 20.574 34.349 ;
     RECT  2.412 34.013 8.097 34.889 ;
     RECT  2.415 34.889 8.097 34.961 ;
     RECT  8.82 34.079 13.662 35.041 ;
     RECT  0.54 34.735 0.558 35.239 ;
     RECT  0.504 35.239 0.558 35.401 ;
     RECT  14.832 34.349 20.538 35.437 ;
     RECT  8.82 35.041 13.698 35.581 ;
     RECT  14.832 35.437 20.574 35.581 ;
     RECT  8.82 35.581 20.574 35.693 ;
     RECT  2.415 34.961 4.266 35.851 ;
     RECT  2.415 35.851 4.302 36.005 ;
     RECT  8.82 35.693 20.07 36.005 ;
     RECT  0.216 35.401 0.558 36.221 ;
     RECT  2.415 36.005 4.266 36.379 ;
     RECT  14.832 36.005 20.07 36.517 ;
     RECT  2.304 36.379 4.266 36.749 ;
     RECT  14.832 36.517 20.502 36.823 ;
     RECT  2.376 36.749 4.266 36.851 ;
     RECT  0.54 36.221 0.558 37.021 ;
     RECT  0.216 37.021 0.558 37.085 ;
     RECT  5.115 34.961 8.097 37.192 ;
     RECT  8.82 36.005 13.662 37.201 ;
     RECT  3.744 36.851 4.266 37.291 ;
     RECT  5.004 37.192 8.097 37.291 ;
     RECT  14.832 36.823 20.574 37.291 ;
     RECT  8.82 37.201 13.806 37.319 ;
     RECT  14.688 37.291 20.574 37.391 ;
     RECT  0.216 37.085 0.522 37.421 ;
     RECT  2.376 36.851 2.97 37.741 ;
     RECT  3.744 37.291 8.097 37.741 ;
     RECT  0.504 37.421 0.522 37.757 ;
     RECT  2.376 37.741 8.097 37.831 ;
     RECT  14.832 37.391 20.574 38.039 ;
     RECT  2.304 37.831 8.097 38.093 ;
     RECT  14.868 38.039 20.574 38.173 ;
     RECT  8.82 37.319 13.662 38.443 ;
     RECT  14.868 38.173 20.61 38.477 ;
     RECT  14.868 38.477 20.538 38.813 ;
     RECT  2.415 38.093 8.097 38.911 ;
     RECT  8.82 38.443 13.698 38.939 ;
     RECT  2.304 38.911 8.097 38.957 ;
     RECT  14.868 38.813 20.07 38.971 ;
     RECT  14.652 38.971 20.07 39.011 ;
     RECT  2.412 38.957 8.097 39.119 ;
     RECT  2.412 39.119 4.266 39.245 ;
     RECT  0.54 38.173 0.558 39.485 ;
     RECT  2.415 39.245 4.266 39.515 ;
     RECT  3.924 39.515 4.266 39.749 ;
     RECT  14.832 39.011 20.07 39.821 ;
     RECT  5.115 39.119 8.097 39.865 ;
     RECT  3.996 39.749 4.266 39.901 ;
     RECT  5.004 39.865 8.097 39.901 ;
     RECT  2.415 39.515 2.862 39.979 ;
     RECT  2.304 39.979 2.862 40.019 ;
     RECT  3.996 39.901 8.097 40.199 ;
     RECT  2.415 40.019 2.862 40.369 ;
     RECT  14.904 39.821 20.07 40.369 ;
     RECT  4.824 40.199 8.097 40.469 ;
     RECT  0.216 40.459 0.234 40.589 ;
     RECT  4.824 40.469 6.03 40.595 ;
     RECT  3.996 40.199 4.05 40.739 ;
     RECT  2.415 40.369 2.97 40.877 ;
     RECT  2.415 40.877 2.862 40.981 ;
     RECT  3.96 40.873 3.978 41.251 ;
     RECT  5.115 40.595 6.03 41.251 ;
     RECT  0.288 41.227 0.306 41.341 ;
     RECT  3.852 41.251 3.978 41.405 ;
     RECT  5.115 41.251 6.066 41.521 ;
     RECT  4.896 41.521 6.066 41.611 ;
     RECT  14.904 40.369 20.538 41.719 ;
     RECT  0.288 41.341 0.558 41.755 ;
     RECT  0.252 41.755 0.558 41.885 ;
     RECT  4.536 41.611 6.066 42.025 ;
     RECT  6.804 40.469 8.097 42.025 ;
     RECT  2.304 40.981 2.862 42.061 ;
     RECT  14.832 41.719 20.538 42.061 ;
     RECT  4.536 42.025 8.097 42.259 ;
     RECT  2.304 42.061 2.97 42.331 ;
     RECT  4.5 42.259 8.097 42.331 ;
     RECT  2.304 42.331 8.097 42.485 ;
     RECT  14.724 42.061 20.538 42.691 ;
     RECT  8.82 38.939 13.662 42.763 ;
     RECT  14.724 42.691 20.574 42.763 ;
     RECT  8.82 42.763 20.574 42.899 ;
     RECT  2.304 42.485 6.57 42.989 ;
     RECT  2.304 42.989 3.402 43.025 ;
     RECT  4.248 42.989 6.57 43.231 ;
     RECT  7.38 42.485 8.097 43.231 ;
     RECT  2.304 43.025 3.078 43.277 ;
     RECT  14.868 42.899 20.574 43.613 ;
     RECT  14.868 43.613 20.07 43.637 ;
     RECT  14.868 43.637 19.998 43.681 ;
     RECT  0.54 41.885 0.558 43.723 ;
     RECT  2.376 43.277 3.078 43.835 ;
     RECT  4.248 43.231 8.097 43.835 ;
     RECT  4.248 43.835 6.534 43.853 ;
     RECT  4.248 43.853 6.174 43.951 ;
     RECT  8.82 42.899 13.626 43.951 ;
     RECT  4.14 43.951 6.174 44.149 ;
     RECT  2.376 43.835 2.862 44.221 ;
     RECT  2.304 44.221 2.862 44.285 ;
     RECT  3.6 44.149 6.174 44.339 ;
     RECT  8.82 43.951 13.662 44.339 ;
     RECT  3.6 44.339 3.726 44.375 ;
     RECT  14.796 43.681 19.998 44.375 ;
     RECT  14.796 44.375 16.938 44.411 ;
     RECT  17.82 44.375 19.998 44.411 ;
     RECT  17.856 44.411 19.998 44.419 ;
     RECT  3.6 44.375 3.618 44.447 ;
     RECT  2.415 44.285 2.862 44.581 ;
     RECT  4.5 44.339 6.174 44.689 ;
     RECT  7.38 43.835 8.097 44.689 ;
     RECT  2.415 44.581 3.51 44.987 ;
     RECT  0.216 43.723 0.558 45.149 ;
     RECT  8.82 44.339 13.59 45.149 ;
     RECT  4.5 44.689 8.097 45.157 ;
     RECT  4.464 45.157 8.097 45.193 ;
     RECT  17.856 44.419 20.538 45.265 ;
     RECT  0.216 45.149 0.234 45.341 ;
     RECT  14.832 44.411 16.866 45.355 ;
     RECT  14.832 45.355 16.902 45.419 ;
     RECT  14.976 45.419 16.902 45.769 ;
     RECT  2.415 44.987 3.33 45.787 ;
     RECT  17.784 45.265 20.538 45.797 ;
     RECT  2.304 45.787 3.33 45.841 ;
     RECT  4.392 45.193 8.097 45.841 ;
     RECT  14.976 45.769 17.046 45.959 ;
     RECT  17.784 45.797 18.918 45.995 ;
     RECT  19.944 45.797 20.538 46.003 ;
     RECT  8.82 45.149 13.497 46.031 ;
     RECT  14.976 45.959 17.01 46.067 ;
     RECT  14.976 46.067 16.974 46.103 ;
     RECT  17.784 45.995 18.897 46.111 ;
     RECT  2.304 45.841 8.097 46.139 ;
     RECT  14.976 46.103 16.83 46.201 ;
     RECT  9.432 46.031 13.497 46.265 ;
     RECT  14.94 46.201 16.83 46.309 ;
     RECT  19.944 46.003 20.574 46.349 ;
     RECT  2.304 46.139 2.862 46.409 ;
     RECT  9.432 46.265 10.926 46.409 ;
     RECT  14.832 46.309 16.83 46.409 ;
     RECT  19.944 46.349 20.502 46.544 ;
     RECT  2.376 46.409 2.862 46.921 ;
     RECT  3.96 46.139 8.097 46.921 ;
     RECT  11.736 46.265 13.497 46.921 ;
     RECT  17.748 46.111 18.897 47.011 ;
     RECT  9.432 46.409 10.797 47.039 ;
     RECT  11.736 46.921 13.806 47.039 ;
     RECT  17.568 47.011 18.897 47.119 ;
     RECT  19.944 46.544 19.998 47.119 ;
     RECT  2.376 46.921 8.097 47.213 ;
     RECT  2.415 47.213 8.097 47.405 ;
     RECT  0.54 47.281 0.558 47.419 ;
     RECT  14.904 46.409 16.83 47.461 ;
     RECT  9.432 47.039 9.45 47.489 ;
     RECT  0.252 47.419 0.558 47.549 ;
     RECT  10.515 47.039 10.797 47.551 ;
     RECT  14.328 47.461 16.83 47.579 ;
     RECT  2.415 47.405 5.994 47.615 ;
     RECT  10.515 47.551 10.854 47.651 ;
     RECT  17.568 47.119 19.998 47.659 ;
     RECT  14.976 47.579 16.83 47.731 ;
     RECT  17.568 47.659 20.538 47.731 ;
     RECT  14.976 47.731 20.538 47.885 ;
     RECT  2.415 47.615 2.826 48.001 ;
     RECT  2.304 48.001 2.826 48.077 ;
     RECT  3.708 47.615 5.994 48.235 ;
     RECT  6.84 47.405 8.097 48.235 ;
     RECT  11.736 47.039 13.497 48.263 ;
     RECT  2.415 48.077 2.826 48.361 ;
     RECT  3.708 48.235 8.097 48.361 ;
     RECT  11.952 48.263 13.497 48.389 ;
     RECT  2.415 48.361 8.097 48.413 ;
     RECT  4.356 48.413 8.097 48.461 ;
     RECT  14.976 47.885 18.897 48.505 ;
     RECT  0.54 47.549 0.558 48.605 ;
     RECT  19.944 47.885 20.538 48.631 ;
     RECT  14.724 48.505 18.897 48.695 ;
     RECT  10.515 47.651 10.797 48.703 ;
     RECT  10.515 48.703 10.854 48.803 ;
     RECT  12.24 48.389 13.497 49.073 ;
     RECT  0.216 48.901 0.234 49.085 ;
     RECT  14.832 48.695 18.897 49.171 ;
     RECT  5.115 48.461 8.097 49.199 ;
     RECT  2.415 48.413 3.402 49.235 ;
     RECT  2.415 49.235 3.078 49.243 ;
     RECT  4.356 48.461 4.374 49.291 ;
     RECT  5.115 49.199 5.994 49.291 ;
     RECT  14.832 49.171 18.918 49.307 ;
     RECT  14.832 49.307 17.874 49.343 ;
     RECT  18.615 49.307 18.918 49.343 ;
     RECT  2.304 49.243 3.078 49.379 ;
     RECT  4.356 49.291 5.994 49.441 ;
     RECT  19.944 48.631 20.574 49.468 ;
     RECT  12.312 49.073 13.497 49.469 ;
     RECT  14.832 49.343 16.794 49.711 ;
     RECT  12.564 49.469 13.497 49.739 ;
     RECT  19.944 49.468 20.61 49.805 ;
     RECT  2.415 49.379 3.078 49.981 ;
     RECT  3.996 49.441 5.994 49.981 ;
     RECT  14.58 49.711 16.794 50.045 ;
     RECT  2.415 49.981 5.994 50.125 ;
     RECT  6.876 49.199 8.097 50.125 ;
     RECT  17.856 49.343 17.874 50.161 ;
     RECT  18.615 49.343 18.897 50.161 ;
     RECT  14.976 50.045 16.794 50.315 ;
     RECT  0.216 49.891 0.234 50.395 ;
     RECT  15.12 50.315 16.794 50.431 ;
     RECT  17.856 50.161 18.897 50.431 ;
     RECT  0.216 50.395 0.306 50.459 ;
     RECT  0.216 50.459 0.234 50.477 ;
     RECT  2.415 50.125 8.097 50.549 ;
     RECT  19.944 49.805 19.962 50.557 ;
     RECT  15.12 50.431 18.897 50.585 ;
     RECT  2.415 50.549 6.642 50.729 ;
     RECT  15.12 50.585 16.758 50.729 ;
     RECT  2.415 50.729 5.994 50.779 ;
     RECT  19.908 50.557 19.962 50.791 ;
     RECT  19.908 50.791 20.538 50.813 ;
     RECT  2.304 50.779 5.994 50.891 ;
     RECT  15.915 50.729 16.758 50.927 ;
     RECT  7.38 50.549 8.097 50.963 ;
     RECT  15.915 50.927 16.722 51.089 ;
     RECT  17.676 50.585 18.897 51.161 ;
     RECT  3.42 50.891 5.994 51.233 ;
     RECT  15.12 50.729 15.138 51.241 ;
     RECT  3.636 51.233 5.994 51.269 ;
     RECT  14.832 51.241 15.138 51.269 ;
     RECT  0.216 51.211 0.234 51.341 ;
     RECT  19.944 50.813 20.538 51.341 ;
     RECT  2.304 50.891 2.697 51.359 ;
     RECT  3.996 51.269 5.994 51.359 ;
     RECT  4.32 51.359 5.994 51.389 ;
     RECT  14.832 51.269 14.85 51.395 ;
     RECT  4.788 51.389 5.994 51.431 ;
     RECT  17.892 51.161 18.897 51.475 ;
     RECT  6.912 51.367 6.93 51.503 ;
     RECT  4.788 51.431 5.397 51.533 ;
     RECT  20.52 51.341 20.538 51.539 ;
     RECT  15.915 51.089 16.542 51.629 ;
     RECT  17.892 51.475 18.954 51.629 ;
     RECT  2.376 51.359 2.697 51.665 ;
     RECT  18.615 51.629 18.954 51.677 ;
     RECT  2.415 51.665 2.697 53.747 ;
     RECT  5.115 51.533 5.397 53.747 ;
     RECT  7.815 50.963 8.097 53.747 ;
     RECT  10.515 48.803 10.797 53.747 ;
     RECT  13.215 49.739 13.497 53.747 ;
     RECT  15.915 51.629 16.197 53.747 ;
     RECT  18.615 51.677 18.897 53.747 ;
     RECT  2.415 53.747 2.505 54.017 ;
     RECT  5.115 53.747 5.205 54.017 ;
     RECT  7.815 53.747 7.905 54.017 ;
     RECT  10.515 53.747 10.605 54.017 ;
     RECT  13.215 53.747 13.305 54.017 ;
     RECT  15.915 53.747 16.005 54.017 ;
     RECT  18.615 53.747 18.705 54.017 ;
    LAYER M4 ;
     RECT  0.156 4.512 2.408 51.672 ;
     RECT  2.408 2.148 2.512 54.012 ;
     RECT  2.512 2.418 2.704 53.742 ;
     RECT  2.704 4.896 2.837 51.528 ;
     RECT  2.837 4.896 3.413 33.144 ;
     RECT  3.413 4.896 4.025 32.904 ;
     RECT  2.837 34.128 4.025 44.232 ;
     RECT  2.837 45.456 4.025 51.528 ;
     RECT  4.025 17.472 4.061 32.904 ;
     RECT  4.025 4.896 4.097 16.344 ;
     RECT  4.025 36.864 4.097 44.232 ;
     RECT  4.097 4.896 5.108 5.496 ;
     RECT  4.097 6.576 5.108 16.344 ;
     RECT  4.061 17.472 5.108 18.024 ;
     RECT  4.061 19.104 5.108 29.112 ;
     RECT  4.061 30.336 5.108 32.904 ;
     RECT  4.025 34.128 5.108 35.784 ;
     RECT  4.097 36.864 5.108 44.136 ;
     RECT  4.025 45.456 5.108 49.32 ;
     RECT  4.025 50.64 5.108 51.528 ;
     RECT  5.108 2.148 5.212 54.012 ;
     RECT  5.212 2.418 5.404 53.742 ;
     RECT  5.404 21.456 5.429 23.64 ;
     RECT  5.404 10.704 5.465 11.448 ;
     RECT  5.404 13.104 5.573 14.952 ;
     RECT  5.404 38.448 5.573 41.784 ;
     RECT  5.465 10.704 5.645 11.16 ;
     RECT  5.429 23.328 5.681 23.64 ;
     RECT  5.404 30.432 5.717 30.984 ;
     RECT  5.404 46.8 5.717 47.4 ;
     RECT  5.404 43.824 5.753 44.136 ;
     RECT  5.429 21.456 5.789 21.72 ;
     RECT  5.404 27.888 5.789 29.016 ;
     RECT  5.573 38.448 6.041 41.448 ;
     RECT  5.404 42.768 6.221 42.792 ;
     RECT  5.573 13.104 6.329 13.896 ;
     RECT  5.404 20.112 6.329 20.376 ;
     RECT  5.789 27.888 6.329 28.824 ;
     RECT  6.041 38.448 6.329 40.056 ;
     RECT  5.404 32.304 6.365 32.328 ;
     RECT  5.717 46.848 6.509 47.4 ;
     RECT  5.404 6.624 6.545 8.808 ;
     RECT  5.753 43.824 6.545 43.848 ;
     RECT  5.404 50.64 6.545 50.664 ;
     RECT  5.404 5.472 6.577 5.496 ;
     RECT  5.404 36.864 6.581 36.888 ;
     RECT  5.645 11.136 6.617 11.16 ;
     RECT  5.404 25.968 6.617 26.616 ;
     RECT  5.404 34.464 6.617 35.736 ;
     RECT  5.717 30.96 6.653 30.984 ;
     RECT  6.329 38.448 6.653 38.472 ;
     RECT  5.789 21.456 6.761 21.48 ;
     RECT  6.617 34.464 6.761 34.488 ;
     RECT  6.577 5.472 7.808 5.64 ;
     RECT  6.545 6.624 7.808 8.28 ;
     RECT  6.329 13.872 7.808 13.896 ;
     RECT  5.573 14.928 7.808 14.952 ;
     RECT  5.404 16.32 7.808 16.344 ;
     RECT  5.404 17.664 7.808 17.688 ;
     RECT  6.329 20.112 7.808 20.136 ;
     RECT  5.681 23.616 7.808 23.64 ;
     RECT  6.617 25.968 7.808 26.088 ;
     RECT  6.329 27.888 7.808 27.912 ;
     RECT  6.617 35.712 7.808 35.736 ;
     RECT  6.329 39.888 7.808 40.056 ;
     RECT  6.041 41.424 7.808 41.448 ;
     RECT  6.509 46.848 7.808 46.872 ;
     RECT  7.808 2.148 7.912 54.012 ;
     RECT  7.912 2.418 8.104 53.742 ;
     RECT  8.104 6.624 10.508 6.648 ;
     RECT  8.104 8.256 10.508 8.28 ;
     RECT  8.104 13.872 10.508 13.896 ;
     RECT  8.104 16.32 10.508 16.344 ;
     RECT  8.104 26.064 10.508 26.088 ;
     RECT  8.104 27.888 10.508 27.912 ;
     RECT  8.104 35.712 10.508 35.736 ;
     RECT  8.104 40.032 10.508 40.056 ;
     RECT  10.508 2.148 10.612 54.012 ;
     RECT  10.612 2.148 10.748 53.742 ;
     RECT  10.748 1.728 10.804 53.742 ;
     RECT  10.804 1.728 10.835 1.752 ;
     RECT  10.804 8.16 10.865 8.28 ;
     RECT  10.804 6.624 11.869 6.648 ;
     RECT  11.869 15.12 11.941 15.144 ;
     RECT  10.804 16.32 11.941 16.344 ;
     RECT  11.869 23.568 11.941 23.592 ;
     RECT  10.804 27.888 11.941 27.912 ;
     RECT  11.869 5.616 11.977 6.648 ;
     RECT  10.865 8.16 11.977 8.184 ;
     RECT  11.941 22.848 12.049 24.12 ;
     RECT  10.804 13.632 12.125 13.896 ;
     RECT  12.013 12.528 12.157 12.552 ;
     RECT  12.013 19.056 12.157 20.088 ;
     RECT  12.049 22.848 12.229 24.936 ;
     RECT  11.941 16.32 12.301 16.44 ;
     RECT  12.229 22.56 12.373 24.936 ;
     RECT  10.804 25.968 12.373 25.992 ;
     RECT  12.037 21.504 12.517 21.528 ;
     RECT  12.373 22.56 12.517 25.992 ;
     RECT  12.125 13.872 12.553 13.896 ;
     RECT  11.941 15.072 12.553 15.144 ;
     RECT  12.157 11.76 12.589 12.552 ;
     RECT  12.589 11.232 12.625 12.552 ;
     RECT  11.941 27.888 12.661 28.296 ;
     RECT  12.517 21.504 12.769 25.992 ;
     RECT  12.157 19.056 12.805 20.28 ;
     RECT  12.769 21.504 12.805 26.568 ;
     RECT  12.301 16.32 12.877 17.64 ;
     RECT  12.877 16.32 12.949 17.736 ;
     RECT  12.805 19.056 12.949 26.568 ;
     RECT  12.949 16.32 13.165 26.568 ;
     RECT  11.977 5.616 13.208 8.184 ;
     RECT  11.905 9.36 13.208 9.384 ;
     RECT  12.625 10.992 13.208 12.552 ;
     RECT  12.553 13.872 13.208 15.144 ;
     RECT  13.165 16.32 13.208 26.904 ;
     RECT  12.661 27.888 13.208 28.44 ;
     RECT  10.804 35.712 13.208 35.736 ;
     RECT  10.804 40.032 13.208 40.056 ;
     RECT  13.208 2.148 13.312 54.012 ;
     RECT  13.312 2.418 13.504 53.742 ;
     RECT  13.504 17.616 13.565 18.216 ;
     RECT  13.504 30.528 13.637 30.792 ;
     RECT  13.504 26.784 13.673 28.008 ;
     RECT  13.637 30.528 13.673 30.552 ;
     RECT  13.504 39.456 14.291 40.056 ;
     RECT  13.504 10.272 14.492 15.096 ;
     RECT  13.504 16.32 14.492 16.344 ;
     RECT  13.504 19.296 14.569 21 ;
     RECT  14.291 39.456 14.641 39.576 ;
     RECT  13.504 5.328 14.677 9.096 ;
     RECT  14.492 10.272 14.677 16.344 ;
     RECT  14.677 5.328 14.681 16.344 ;
     RECT  14.681 5.712 14.869 16.344 ;
     RECT  13.565 17.904 14.869 18.216 ;
     RECT  14.869 5.712 14.929 18.216 ;
     RECT  14.569 19.296 14.929 21.096 ;
     RECT  14.929 5.712 15.001 21.096 ;
     RECT  14.893 34.56 15.037 34.584 ;
     RECT  15.001 5.712 15.073 21.192 ;
     RECT  14.893 33.168 15.073 33.192 ;
     RECT  14.965 28.896 15.181 29.016 ;
     RECT  13.504 22.848 15.217 22.872 ;
     RECT  13.504 23.952 15.217 25.8 ;
     RECT  13.673 26.784 15.217 27.912 ;
     RECT  14.821 31.152 15.325 31.176 ;
     RECT  15.073 32.4 15.325 33.192 ;
     RECT  15.073 5.712 15.637 21.24 ;
     RECT  15.217 22.512 15.637 22.872 ;
     RECT  15.289 4.512 15.908 4.536 ;
     RECT  15.637 5.712 15.908 22.872 ;
     RECT  15.217 23.952 15.908 27.912 ;
     RECT  15.181 28.896 15.908 29.064 ;
     RECT  15.325 31.152 15.908 33.192 ;
     RECT  15.037 34.56 15.908 34.68 ;
     RECT  13.504 35.712 15.908 35.736 ;
     RECT  14.641 38.976 15.908 39.576 ;
     RECT  14.857 42.048 15.908 42.072 ;
     RECT  15.109 43.344 15.908 43.368 ;
     RECT  15.908 2.148 16.012 54.012 ;
     RECT  16.012 2.418 16.204 53.742 ;
     RECT  16.204 39.552 16.451 41.448 ;
     RECT  16.204 31.344 16.499 31.368 ;
     RECT  16.451 39.552 16.517 39.912 ;
     RECT  16.204 44.016 16.636 44.04 ;
     RECT  16.204 36.72 16.643 36.744 ;
     RECT  16.451 41.184 16.691 41.448 ;
     RECT  16.204 4.512 16.787 29.064 ;
     RECT  16.204 35.712 16.835 35.736 ;
     RECT  16.691 41.424 16.877 41.448 ;
     RECT  16.787 4.512 16.913 8.28 ;
     RECT  16.787 9.312 17.021 29.064 ;
     RECT  17.021 9.36 17.093 29.064 ;
     RECT  17.093 9.36 17.123 28.968 ;
     RECT  16.204 46.704 17.123 48.072 ;
     RECT  16.913 4.512 17.165 8.136 ;
     RECT  17.123 48.048 17.171 48.072 ;
     RECT  17.123 46.704 17.219 46.776 ;
     RECT  16.204 45.36 17.267 45.384 ;
     RECT  17.42 49.152 17.507 49.176 ;
     RECT  17.665 43.824 17.837 43.848 ;
     RECT  17.123 9.36 18.161 15 ;
     RECT  17.165 4.56 18.181 8.136 ;
     RECT  17.665 30.864 18.205 30.888 ;
     RECT  17.123 16.32 18.313 28.536 ;
     RECT  18.161 9.36 18.421 15.048 ;
     RECT  18.205 30.864 18.421 31.512 ;
     RECT  18.421 9.36 18.529 15.24 ;
     RECT  18.181 3.84 18.608 8.136 ;
     RECT  18.529 9.264 18.608 15.24 ;
     RECT  18.313 16.32 18.608 29.256 ;
     RECT  18.421 30.864 18.608 31.944 ;
     RECT  17.917 33.792 18.608 33.816 ;
     RECT  16.517 39.552 18.608 39.576 ;
     RECT  17.837 43.824 18.608 44.472 ;
     RECT  17.219 46.752 18.608 46.776 ;
     RECT  18.061 48.48 18.608 48.504 ;
     RECT  17.881 51.312 18.608 51.336 ;
     RECT  18.608 2.148 18.712 54.012 ;
     RECT  18.712 2.418 18.904 53.742 ;
     RECT  18.904 3.696 19.139 31.944 ;
     RECT  19.139 3.936 19.187 31.944 ;
     RECT  18.904 50.112 19.897 50.664 ;
     RECT  18.904 51.648 19.897 51.672 ;
     RECT  19.187 4.512 19.933 31.944 ;
     RECT  18.904 32.928 19.933 36.888 ;
     RECT  18.904 38.064 19.933 38.088 ;
     RECT  18.904 39.648 19.933 45.48 ;
     RECT  18.904 47.184 19.933 47.88 ;
     RECT  19.897 50.112 19.933 51.672 ;
     RECT  19.933 4.512 21.42 51.672 ;
     RECT  21.42 9.552 21.485 9.576 ;
     RECT  21.42 11.952 21.485 11.976 ;
     RECT  21.42 29.088 21.485 29.112 ;
    LAYER M5 ;
     RECT  10.8 0.144 10.824 1.763 ;
     RECT  10.8 1.763 10.812 2.137 ;
     RECT  2.4 2.137 2.52 2.151 ;
     RECT  5.1 2.137 5.22 2.151 ;
     RECT  7.8 2.137 7.92 2.151 ;
     RECT  13.2 2.137 13.32 2.151 ;
     RECT  15.9 2.137 16.02 2.151 ;
     RECT  18.6 2.137 18.72 2.151 ;
     RECT  18.6 2.151 18.912 3.685 ;
     RECT  18.6 3.685 19.128 3.829 ;
     RECT  18.192 3.829 19.128 3.925 ;
     RECT  15.9 2.151 16.212 4.501 ;
     RECT  18.192 3.925 19.176 4.501 ;
     RECT  15.312 4.501 17.112 5.077 ;
     RECT  18.192 4.501 19.224 5.077 ;
     RECT  15.312 5.077 19.224 5.747 ;
     RECT  15.312 5.747 16.344 5.989 ;
     RECT  17.712 5.747 19.224 6.085 ;
     RECT  17.712 6.085 19.32 6.421 ;
     RECT  15.168 5.989 16.344 6.805 ;
     RECT  17.712 6.421 19.368 7.379 ;
     RECT  15.168 6.805 16.728 9.013 ;
     RECT  17.712 7.379 19.032 9.013 ;
     RECT  15.168 9.013 19.032 9.731 ;
     RECT  15.168 9.731 16.728 9.923 ;
     RECT  17.712 9.731 19.032 10.021 ;
     RECT  17.712 10.021 19.368 10.883 ;
     RECT  15.168 9.923 16.488 11.365 ;
     RECT  17.712 10.883 19.032 11.365 ;
     RECT  15.168 11.365 19.032 12.995 ;
     RECT  15.168 12.995 18.912 13.045 ;
     RECT  14.88 13.045 18.912 13.187 ;
     RECT  17.712 13.187 18.912 13.957 ;
     RECT  14.88 13.187 16.632 14.629 ;
     RECT  17.712 13.957 19.032 14.629 ;
     RECT  14.88 14.629 19.032 14.725 ;
     RECT  14.88 14.725 19.368 15.395 ;
     RECT  14.88 15.395 19.032 15.443 ;
     RECT  17.712 15.443 19.032 15.731 ;
     RECT  14.88 15.443 16.632 15.829 ;
     RECT  14.544 15.829 16.632 16.355 ;
     RECT  14.736 16.355 16.632 16.933 ;
     RECT  17.712 15.731 18.912 16.933 ;
     RECT  14.736 16.933 18.912 17.461 ;
     RECT  14.736 17.461 19.032 18.323 ;
     RECT  14.736 18.323 18.912 19.619 ;
     RECT  14.736 19.619 16.68 21.013 ;
     RECT  17.712 19.619 18.912 21.013 ;
     RECT  14.736 21.013 18.912 21.397 ;
     RECT  2.4 2.151 2.712 21.493 ;
     RECT  2.304 21.493 2.712 21.683 ;
     RECT  13.2 2.151 13.512 21.733 ;
     RECT  14.736 21.397 19.032 22.067 ;
     RECT  14.736 22.067 18.912 23.125 ;
     RECT  2.4 21.683 2.712 23.221 ;
     RECT  2.304 23.221 2.712 23.363 ;
     RECT  12.048 21.493 12.072 23.411 ;
     RECT  14.736 23.125 19.128 23.651 ;
     RECT  13.104 21.733 13.512 24.709 ;
     RECT  14.736 23.651 19.032 24.851 ;
     RECT  13.104 24.709 13.656 25.571 ;
     RECT  14.736 24.851 18.912 26.341 ;
     RECT  14.736 26.341 19.368 26.819 ;
     RECT  13.104 25.571 13.608 27.013 ;
     RECT  2.4 23.363 2.712 27.541 ;
     RECT  2.304 27.541 2.712 27.683 ;
     RECT  13.104 27.013 13.656 28.019 ;
     RECT  13.104 28.019 13.512 28.355 ;
     RECT  14.736 26.819 19.176 29.795 ;
     RECT  2.4 27.683 2.712 29.893 ;
     RECT  2.304 29.893 2.712 30.083 ;
     RECT  13.2 28.355 13.512 30.517 ;
     RECT  14.736 29.795 18.912 30.757 ;
     RECT  13.2 30.517 13.608 30.803 ;
     RECT  2.4 30.083 2.712 31.477 ;
     RECT  14.736 30.757 19.512 31.523 ;
     RECT  2.304 31.477 2.712 31.667 ;
     RECT  13.2 30.803 13.512 39.445 ;
     RECT  14.736 31.523 18.912 39.445 ;
     RECT  13.2 39.445 18.912 40.067 ;
     RECT  15.072 40.067 18.912 42.083 ;
     RECT  15.12 42.083 18.912 43.379 ;
     RECT  2.4 31.667 2.712 46.165 ;
     RECT  2.256 46.165 2.712 46.307 ;
     RECT  2.304 46.307 2.712 47.027 ;
     RECT  15.9 43.379 18.912 48.083 ;
     RECT  17.472 48.083 18.912 49.187 ;
     RECT  17.904 49.187 18.912 51.347 ;
     RECT  0.24 51.205 0.264 51.395 ;
     RECT  2.4 47.027 2.712 54.009 ;
     RECT  5.1 2.151 5.412 54.009 ;
     RECT  7.8 2.151 8.112 54.009 ;
     RECT  10.5 2.137 10.812 54.009 ;
     RECT  13.2 40.067 13.512 54.009 ;
     RECT  15.9 48.083 16.212 54.009 ;
     RECT  18.6 51.347 18.912 54.009 ;
     RECT  2.4 54.009 2.52 54.023 ;
     RECT  5.1 54.009 5.22 54.023 ;
     RECT  7.8 54.009 7.92 54.023 ;
     RECT  10.5 54.009 10.62 54.023 ;
     RECT  13.2 54.009 13.32 54.023 ;
     RECT  15.9 54.009 16.02 54.023 ;
     RECT  18.6 54.009 18.72 54.023 ;
  END
END hbfd_rly_136_EW_fc_f3
END LIBRARY
